# Generated by FakeRAM 2.0 (routing-friendly)
VERSION 5.7 ;
BUSBITCHARS "[]" ;
PROPERTYDEFINITIONS
  MACRO width INTEGER ;
  MACRO depth INTEGER ;
  MACRO banks INTEGER ;
END PROPERTYDEFINITIONS
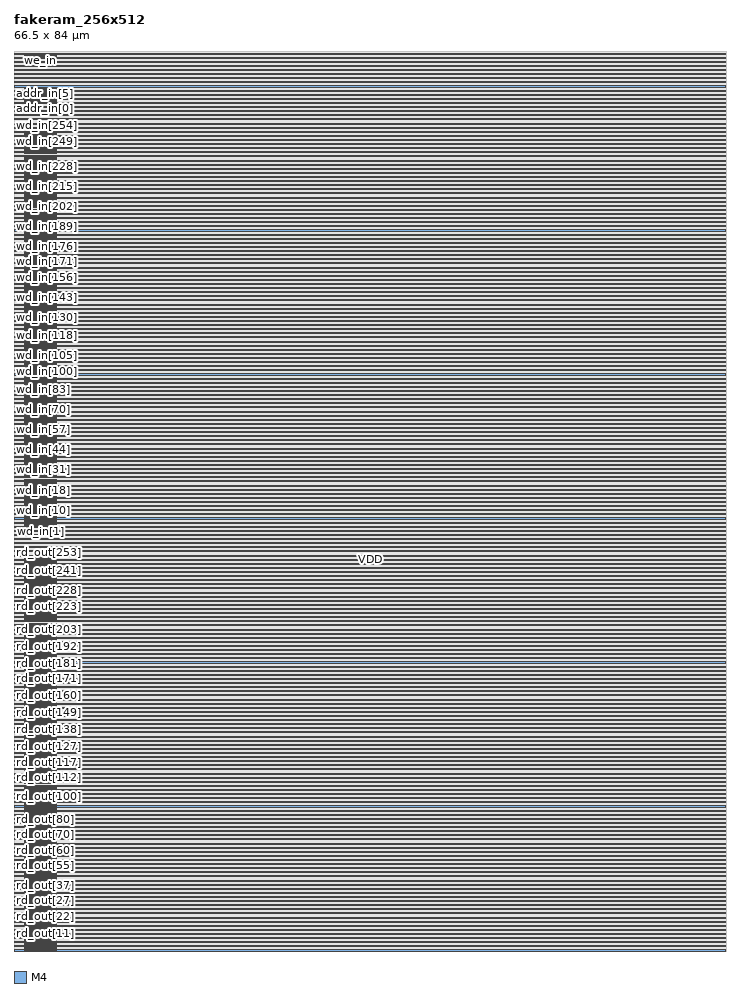
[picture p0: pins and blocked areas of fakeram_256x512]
MACRO fakeram_256x512
  PROPERTY width 256 ;
  PROPERTY depth 512 ;
  PROPERTY banks 2 ;
  FOREIGN fakeram_256x512 0 0 ;
  SYMMETRY X Y R90 ;
  SIZE 66.500 BY 84.000 ;
  CLASS BLOCK ;
  PIN rd_out[0]
    DIRECTION OUTPUT ;
    USE SIGNAL ;
    PORT
      LAYER M4 ;
      RECT 1.000 0.048 3.000 0.072 ;
    END
    PORT
      LAYER M4 ;
      RECT 1.000 0.036 4.000 0.084 ;
    END
  END rd_out[0]
  PIN rd_out[1]
    DIRECTION OUTPUT ;
    USE SIGNAL ;
    PORT
      LAYER M4 ;
      RECT 1.000 0.192 3.000 0.216 ;
    END
    PORT
      LAYER M4 ;
      RECT 1.000 0.180 4.000 0.228 ;
    END
  END rd_out[1]
  PIN rd_out[2]
    DIRECTION OUTPUT ;
    USE SIGNAL ;
    PORT
      LAYER M4 ;
      RECT 1.000 0.336 3.000 0.360 ;
    END
    PORT
      LAYER M4 ;
      RECT 1.000 0.324 4.000 0.372 ;
    END
  END rd_out[2]
  PIN rd_out[3]
    DIRECTION OUTPUT ;
    USE SIGNAL ;
    PORT
      LAYER M4 ;
      RECT 1.000 0.480 3.000 0.504 ;
    END
    PORT
      LAYER M4 ;
      RECT 1.000 0.468 4.000 0.516 ;
    END
  END rd_out[3]
  PIN rd_out[4]
    DIRECTION OUTPUT ;
    USE SIGNAL ;
    PORT
      LAYER M4 ;
      RECT 1.000 0.624 3.000 0.648 ;
    END
    PORT
      LAYER M4 ;
      RECT 1.000 0.612 4.000 0.660 ;
    END
  END rd_out[4]
  PIN rd_out[5]
    DIRECTION OUTPUT ;
    USE SIGNAL ;
    PORT
      LAYER M4 ;
      RECT 1.000 0.768 3.000 0.792 ;
    END
    PORT
      LAYER M4 ;
      RECT 1.000 0.756 4.000 0.804 ;
    END
  END rd_out[5]
  PIN rd_out[6]
    DIRECTION OUTPUT ;
    USE SIGNAL ;
    PORT
      LAYER M4 ;
      RECT 1.000 0.912 3.000 0.936 ;
    END
    PORT
      LAYER M4 ;
      RECT 1.000 0.900 4.000 0.948 ;
    END
  END rd_out[6]
  PIN rd_out[7]
    DIRECTION OUTPUT ;
    USE SIGNAL ;
    PORT
      LAYER M4 ;
      RECT 1.000 1.056 3.000 1.080 ;
    END
    PORT
      LAYER M4 ;
      RECT 1.000 1.044 4.000 1.092 ;
    END
  END rd_out[7]
  PIN rd_out[8]
    DIRECTION OUTPUT ;
    USE SIGNAL ;
    PORT
      LAYER M4 ;
      RECT 1.000 1.200 3.000 1.224 ;
    END
    PORT
      LAYER M4 ;
      RECT 1.000 1.188 4.000 1.236 ;
    END
  END rd_out[8]
  PIN rd_out[9]
    DIRECTION OUTPUT ;
    USE SIGNAL ;
    PORT
      LAYER M4 ;
      RECT 1.000 1.344 3.000 1.368 ;
    END
    PORT
      LAYER M4 ;
      RECT 1.000 1.332 4.000 1.380 ;
    END
  END rd_out[9]
  PIN rd_out[10]
    DIRECTION OUTPUT ;
    USE SIGNAL ;
    PORT
      LAYER M4 ;
      RECT 1.000 1.488 3.000 1.512 ;
    END
    PORT
      LAYER M4 ;
      RECT 1.000 1.476 4.000 1.524 ;
    END
  END rd_out[10]
  PIN rd_out[11]
    DIRECTION OUTPUT ;
    USE SIGNAL ;
    PORT
      LAYER M4 ;
      RECT 1.000 1.632 3.000 1.656 ;
    END
    PORT
      LAYER M4 ;
      RECT 1.000 1.620 4.000 1.668 ;
    END
  END rd_out[11]
  PIN rd_out[12]
    DIRECTION OUTPUT ;
    USE SIGNAL ;
    PORT
      LAYER M4 ;
      RECT 1.000 1.776 3.000 1.800 ;
    END
    PORT
      LAYER M4 ;
      RECT 1.000 1.764 4.000 1.812 ;
    END
  END rd_out[12]
  PIN rd_out[13]
    DIRECTION OUTPUT ;
    USE SIGNAL ;
    PORT
      LAYER M4 ;
      RECT 1.000 1.920 3.000 1.944 ;
    END
    PORT
      LAYER M4 ;
      RECT 1.000 1.908 4.000 1.956 ;
    END
  END rd_out[13]
  PIN rd_out[14]
    DIRECTION OUTPUT ;
    USE SIGNAL ;
    PORT
      LAYER M4 ;
      RECT 1.000 2.064 3.000 2.088 ;
    END
    PORT
      LAYER M4 ;
      RECT 1.000 2.052 4.000 2.100 ;
    END
  END rd_out[14]
  PIN rd_out[15]
    DIRECTION OUTPUT ;
    USE SIGNAL ;
    PORT
      LAYER M4 ;
      RECT 1.000 2.208 3.000 2.232 ;
    END
    PORT
      LAYER M4 ;
      RECT 1.000 2.196 4.000 2.244 ;
    END
  END rd_out[15]
  PIN rd_out[16]
    DIRECTION OUTPUT ;
    USE SIGNAL ;
    PORT
      LAYER M4 ;
      RECT 1.000 2.352 3.000 2.376 ;
    END
    PORT
      LAYER M4 ;
      RECT 1.000 2.340 4.000 2.388 ;
    END
  END rd_out[16]
  PIN rd_out[17]
    DIRECTION OUTPUT ;
    USE SIGNAL ;
    PORT
      LAYER M4 ;
      RECT 1.000 2.496 3.000 2.520 ;
    END
    PORT
      LAYER M4 ;
      RECT 1.000 2.484 4.000 2.532 ;
    END
  END rd_out[17]
  PIN rd_out[18]
    DIRECTION OUTPUT ;
    USE SIGNAL ;
    PORT
      LAYER M4 ;
      RECT 1.000 2.640 3.000 2.664 ;
    END
    PORT
      LAYER M4 ;
      RECT 1.000 2.628 4.000 2.676 ;
    END
  END rd_out[18]
  PIN rd_out[19]
    DIRECTION OUTPUT ;
    USE SIGNAL ;
    PORT
      LAYER M4 ;
      RECT 1.000 2.784 3.000 2.808 ;
    END
    PORT
      LAYER M4 ;
      RECT 1.000 2.772 4.000 2.820 ;
    END
  END rd_out[19]
  PIN rd_out[20]
    DIRECTION OUTPUT ;
    USE SIGNAL ;
    PORT
      LAYER M4 ;
      RECT 1.000 2.928 3.000 2.952 ;
    END
    PORT
      LAYER M4 ;
      RECT 1.000 2.916 4.000 2.964 ;
    END
  END rd_out[20]
  PIN rd_out[21]
    DIRECTION OUTPUT ;
    USE SIGNAL ;
    PORT
      LAYER M4 ;
      RECT 1.000 3.072 3.000 3.096 ;
    END
    PORT
      LAYER M4 ;
      RECT 1.000 3.060 4.000 3.108 ;
    END
  END rd_out[21]
  PIN rd_out[22]
    DIRECTION OUTPUT ;
    USE SIGNAL ;
    PORT
      LAYER M4 ;
      RECT 1.000 3.216 3.000 3.240 ;
    END
    PORT
      LAYER M4 ;
      RECT 1.000 3.204 4.000 3.252 ;
    END
  END rd_out[22]
  PIN rd_out[23]
    DIRECTION OUTPUT ;
    USE SIGNAL ;
    PORT
      LAYER M4 ;
      RECT 1.000 3.360 3.000 3.384 ;
    END
    PORT
      LAYER M4 ;
      RECT 1.000 3.348 4.000 3.396 ;
    END
  END rd_out[23]
  PIN rd_out[24]
    DIRECTION OUTPUT ;
    USE SIGNAL ;
    PORT
      LAYER M4 ;
      RECT 1.000 3.504 3.000 3.528 ;
    END
    PORT
      LAYER M4 ;
      RECT 1.000 3.492 4.000 3.540 ;
    END
  END rd_out[24]
  PIN rd_out[25]
    DIRECTION OUTPUT ;
    USE SIGNAL ;
    PORT
      LAYER M4 ;
      RECT 1.000 3.648 3.000 3.672 ;
    END
    PORT
      LAYER M4 ;
      RECT 1.000 3.636 4.000 3.684 ;
    END
  END rd_out[25]
  PIN rd_out[26]
    DIRECTION OUTPUT ;
    USE SIGNAL ;
    PORT
      LAYER M4 ;
      RECT 1.000 3.792 3.000 3.816 ;
    END
    PORT
      LAYER M4 ;
      RECT 1.000 3.780 4.000 3.828 ;
    END
  END rd_out[26]
  PIN rd_out[27]
    DIRECTION OUTPUT ;
    USE SIGNAL ;
    PORT
      LAYER M4 ;
      RECT 1.000 3.936 3.000 3.960 ;
    END
    PORT
      LAYER M4 ;
      RECT 1.000 3.924 4.000 3.972 ;
    END
  END rd_out[27]
  PIN rd_out[28]
    DIRECTION OUTPUT ;
    USE SIGNAL ;
    PORT
      LAYER M4 ;
      RECT 1.000 4.080 3.000 4.104 ;
    END
    PORT
      LAYER M4 ;
      RECT 1.000 4.068 4.000 4.116 ;
    END
  END rd_out[28]
  PIN rd_out[29]
    DIRECTION OUTPUT ;
    USE SIGNAL ;
    PORT
      LAYER M4 ;
      RECT 1.000 4.224 3.000 4.248 ;
    END
    PORT
      LAYER M4 ;
      RECT 1.000 4.212 4.000 4.260 ;
    END
  END rd_out[29]
  PIN rd_out[30]
    DIRECTION OUTPUT ;
    USE SIGNAL ;
    PORT
      LAYER M4 ;
      RECT 1.000 4.368 3.000 4.392 ;
    END
    PORT
      LAYER M4 ;
      RECT 1.000 4.356 4.000 4.404 ;
    END
  END rd_out[30]
  PIN rd_out[31]
    DIRECTION OUTPUT ;
    USE SIGNAL ;
    PORT
      LAYER M4 ;
      RECT 1.000 4.512 3.000 4.536 ;
    END
    PORT
      LAYER M4 ;
      RECT 1.000 4.500 4.000 4.548 ;
    END
  END rd_out[31]
  PIN rd_out[32]
    DIRECTION OUTPUT ;
    USE SIGNAL ;
    PORT
      LAYER M4 ;
      RECT 1.000 4.656 3.000 4.680 ;
    END
    PORT
      LAYER M4 ;
      RECT 1.000 4.644 4.000 4.692 ;
    END
  END rd_out[32]
  PIN rd_out[33]
    DIRECTION OUTPUT ;
    USE SIGNAL ;
    PORT
      LAYER M4 ;
      RECT 1.000 4.800 3.000 4.824 ;
    END
    PORT
      LAYER M4 ;
      RECT 1.000 4.788 4.000 4.836 ;
    END
  END rd_out[33]
  PIN rd_out[34]
    DIRECTION OUTPUT ;
    USE SIGNAL ;
    PORT
      LAYER M4 ;
      RECT 1.000 4.944 3.000 4.968 ;
    END
    PORT
      LAYER M4 ;
      RECT 1.000 4.932 4.000 4.980 ;
    END
  END rd_out[34]
  PIN rd_out[35]
    DIRECTION OUTPUT ;
    USE SIGNAL ;
    PORT
      LAYER M4 ;
      RECT 1.000 5.088 3.000 5.112 ;
    END
    PORT
      LAYER M4 ;
      RECT 1.000 5.076 4.000 5.124 ;
    END
  END rd_out[35]
  PIN rd_out[36]
    DIRECTION OUTPUT ;
    USE SIGNAL ;
    PORT
      LAYER M4 ;
      RECT 1.000 5.232 3.000 5.256 ;
    END
    PORT
      LAYER M4 ;
      RECT 1.000 5.220 4.000 5.268 ;
    END
  END rd_out[36]
  PIN rd_out[37]
    DIRECTION OUTPUT ;
    USE SIGNAL ;
    PORT
      LAYER M4 ;
      RECT 1.000 5.376 3.000 5.400 ;
    END
    PORT
      LAYER M4 ;
      RECT 1.000 5.364 4.000 5.412 ;
    END
  END rd_out[37]
  PIN rd_out[38]
    DIRECTION OUTPUT ;
    USE SIGNAL ;
    PORT
      LAYER M4 ;
      RECT 1.000 5.520 3.000 5.544 ;
    END
    PORT
      LAYER M4 ;
      RECT 1.000 5.508 4.000 5.556 ;
    END
  END rd_out[38]
  PIN rd_out[39]
    DIRECTION OUTPUT ;
    USE SIGNAL ;
    PORT
      LAYER M4 ;
      RECT 1.000 5.664 3.000 5.688 ;
    END
    PORT
      LAYER M4 ;
      RECT 1.000 5.652 4.000 5.700 ;
    END
  END rd_out[39]
  PIN rd_out[40]
    DIRECTION OUTPUT ;
    USE SIGNAL ;
    PORT
      LAYER M4 ;
      RECT 1.000 5.808 3.000 5.832 ;
    END
    PORT
      LAYER M4 ;
      RECT 1.000 5.796 4.000 5.844 ;
    END
  END rd_out[40]
  PIN rd_out[41]
    DIRECTION OUTPUT ;
    USE SIGNAL ;
    PORT
      LAYER M4 ;
      RECT 1.000 5.952 3.000 5.976 ;
    END
    PORT
      LAYER M4 ;
      RECT 1.000 5.940 4.000 5.988 ;
    END
  END rd_out[41]
  PIN rd_out[42]
    DIRECTION OUTPUT ;
    USE SIGNAL ;
    PORT
      LAYER M4 ;
      RECT 1.000 6.096 3.000 6.120 ;
    END
    PORT
      LAYER M4 ;
      RECT 1.000 6.084 4.000 6.132 ;
    END
  END rd_out[42]
  PIN rd_out[43]
    DIRECTION OUTPUT ;
    USE SIGNAL ;
    PORT
      LAYER M4 ;
      RECT 1.000 6.240 3.000 6.264 ;
    END
    PORT
      LAYER M4 ;
      RECT 1.000 6.228 4.000 6.276 ;
    END
  END rd_out[43]
  PIN rd_out[44]
    DIRECTION OUTPUT ;
    USE SIGNAL ;
    PORT
      LAYER M4 ;
      RECT 1.000 6.384 3.000 6.408 ;
    END
    PORT
      LAYER M4 ;
      RECT 1.000 6.372 4.000 6.420 ;
    END
  END rd_out[44]
  PIN rd_out[45]
    DIRECTION OUTPUT ;
    USE SIGNAL ;
    PORT
      LAYER M4 ;
      RECT 1.000 6.528 3.000 6.552 ;
    END
    PORT
      LAYER M4 ;
      RECT 1.000 6.516 4.000 6.564 ;
    END
  END rd_out[45]
  PIN rd_out[46]
    DIRECTION OUTPUT ;
    USE SIGNAL ;
    PORT
      LAYER M4 ;
      RECT 1.000 6.672 3.000 6.696 ;
    END
    PORT
      LAYER M4 ;
      RECT 1.000 6.660 4.000 6.708 ;
    END
  END rd_out[46]
  PIN rd_out[47]
    DIRECTION OUTPUT ;
    USE SIGNAL ;
    PORT
      LAYER M4 ;
      RECT 1.000 6.816 3.000 6.840 ;
    END
    PORT
      LAYER M4 ;
      RECT 1.000 6.804 4.000 6.852 ;
    END
  END rd_out[47]
  PIN rd_out[48]
    DIRECTION OUTPUT ;
    USE SIGNAL ;
    PORT
      LAYER M4 ;
      RECT 1.000 6.960 3.000 6.984 ;
    END
    PORT
      LAYER M4 ;
      RECT 1.000 6.948 4.000 6.996 ;
    END
  END rd_out[48]
  PIN rd_out[49]
    DIRECTION OUTPUT ;
    USE SIGNAL ;
    PORT
      LAYER M4 ;
      RECT 1.000 7.104 3.000 7.128 ;
    END
    PORT
      LAYER M4 ;
      RECT 1.000 7.092 4.000 7.140 ;
    END
  END rd_out[49]
  PIN rd_out[50]
    DIRECTION OUTPUT ;
    USE SIGNAL ;
    PORT
      LAYER M4 ;
      RECT 1.000 7.248 3.000 7.272 ;
    END
    PORT
      LAYER M4 ;
      RECT 1.000 7.236 4.000 7.284 ;
    END
  END rd_out[50]
  PIN rd_out[51]
    DIRECTION OUTPUT ;
    USE SIGNAL ;
    PORT
      LAYER M4 ;
      RECT 1.000 7.392 3.000 7.416 ;
    END
    PORT
      LAYER M4 ;
      RECT 1.000 7.380 4.000 7.428 ;
    END
  END rd_out[51]
  PIN rd_out[52]
    DIRECTION OUTPUT ;
    USE SIGNAL ;
    PORT
      LAYER M4 ;
      RECT 1.000 7.536 3.000 7.560 ;
    END
    PORT
      LAYER M4 ;
      RECT 1.000 7.524 4.000 7.572 ;
    END
  END rd_out[52]
  PIN rd_out[53]
    DIRECTION OUTPUT ;
    USE SIGNAL ;
    PORT
      LAYER M4 ;
      RECT 1.000 7.680 3.000 7.704 ;
    END
    PORT
      LAYER M4 ;
      RECT 1.000 7.668 4.000 7.716 ;
    END
  END rd_out[53]
  PIN rd_out[54]
    DIRECTION OUTPUT ;
    USE SIGNAL ;
    PORT
      LAYER M4 ;
      RECT 1.000 7.824 3.000 7.848 ;
    END
    PORT
      LAYER M4 ;
      RECT 1.000 7.812 4.000 7.860 ;
    END
  END rd_out[54]
  PIN rd_out[55]
    DIRECTION OUTPUT ;
    USE SIGNAL ;
    PORT
      LAYER M4 ;
      RECT 1.000 7.968 3.000 7.992 ;
    END
    PORT
      LAYER M4 ;
      RECT 1.000 7.956 4.000 8.004 ;
    END
  END rd_out[55]
  PIN rd_out[56]
    DIRECTION OUTPUT ;
    USE SIGNAL ;
    PORT
      LAYER M4 ;
      RECT 1.000 8.112 3.000 8.136 ;
    END
    PORT
      LAYER M4 ;
      RECT 1.000 8.100 4.000 8.148 ;
    END
  END rd_out[56]
  PIN rd_out[57]
    DIRECTION OUTPUT ;
    USE SIGNAL ;
    PORT
      LAYER M4 ;
      RECT 1.000 8.256 3.000 8.280 ;
    END
    PORT
      LAYER M4 ;
      RECT 1.000 8.244 4.000 8.292 ;
    END
  END rd_out[57]
  PIN rd_out[58]
    DIRECTION OUTPUT ;
    USE SIGNAL ;
    PORT
      LAYER M4 ;
      RECT 1.000 8.400 3.000 8.424 ;
    END
    PORT
      LAYER M4 ;
      RECT 1.000 8.388 4.000 8.436 ;
    END
  END rd_out[58]
  PIN rd_out[59]
    DIRECTION OUTPUT ;
    USE SIGNAL ;
    PORT
      LAYER M4 ;
      RECT 1.000 8.544 3.000 8.568 ;
    END
    PORT
      LAYER M4 ;
      RECT 1.000 8.532 4.000 8.580 ;
    END
  END rd_out[59]
  PIN rd_out[60]
    DIRECTION OUTPUT ;
    USE SIGNAL ;
    PORT
      LAYER M4 ;
      RECT 1.000 8.688 3.000 8.712 ;
    END
    PORT
      LAYER M4 ;
      RECT 1.000 8.676 4.000 8.724 ;
    END
  END rd_out[60]
  PIN rd_out[61]
    DIRECTION OUTPUT ;
    USE SIGNAL ;
    PORT
      LAYER M4 ;
      RECT 1.000 8.832 3.000 8.856 ;
    END
    PORT
      LAYER M4 ;
      RECT 1.000 8.820 4.000 8.868 ;
    END
  END rd_out[61]
  PIN rd_out[62]
    DIRECTION OUTPUT ;
    USE SIGNAL ;
    PORT
      LAYER M4 ;
      RECT 1.000 8.976 3.000 9.000 ;
    END
    PORT
      LAYER M4 ;
      RECT 1.000 8.964 4.000 9.012 ;
    END
  END rd_out[62]
  PIN rd_out[63]
    DIRECTION OUTPUT ;
    USE SIGNAL ;
    PORT
      LAYER M4 ;
      RECT 1.000 9.120 3.000 9.144 ;
    END
    PORT
      LAYER M4 ;
      RECT 1.000 9.108 4.000 9.156 ;
    END
  END rd_out[63]
  PIN rd_out[64]
    DIRECTION OUTPUT ;
    USE SIGNAL ;
    PORT
      LAYER M4 ;
      RECT 1.000 9.264 3.000 9.288 ;
    END
    PORT
      LAYER M4 ;
      RECT 1.000 9.252 4.000 9.300 ;
    END
  END rd_out[64]
  PIN rd_out[65]
    DIRECTION OUTPUT ;
    USE SIGNAL ;
    PORT
      LAYER M4 ;
      RECT 1.000 9.408 3.000 9.432 ;
    END
    PORT
      LAYER M4 ;
      RECT 1.000 9.396 4.000 9.444 ;
    END
  END rd_out[65]
  PIN rd_out[66]
    DIRECTION OUTPUT ;
    USE SIGNAL ;
    PORT
      LAYER M4 ;
      RECT 1.000 9.552 3.000 9.576 ;
    END
    PORT
      LAYER M4 ;
      RECT 1.000 9.540 4.000 9.588 ;
    END
  END rd_out[66]
  PIN rd_out[67]
    DIRECTION OUTPUT ;
    USE SIGNAL ;
    PORT
      LAYER M4 ;
      RECT 1.000 9.696 3.000 9.720 ;
    END
    PORT
      LAYER M4 ;
      RECT 1.000 9.684 4.000 9.732 ;
    END
  END rd_out[67]
  PIN rd_out[68]
    DIRECTION OUTPUT ;
    USE SIGNAL ;
    PORT
      LAYER M4 ;
      RECT 1.000 9.840 3.000 9.864 ;
    END
    PORT
      LAYER M4 ;
      RECT 1.000 9.828 4.000 9.876 ;
    END
  END rd_out[68]
  PIN rd_out[69]
    DIRECTION OUTPUT ;
    USE SIGNAL ;
    PORT
      LAYER M4 ;
      RECT 1.000 9.984 3.000 10.008 ;
    END
    PORT
      LAYER M4 ;
      RECT 1.000 9.972 4.000 10.020 ;
    END
  END rd_out[69]
  PIN rd_out[70]
    DIRECTION OUTPUT ;
    USE SIGNAL ;
    PORT
      LAYER M4 ;
      RECT 1.000 10.128 3.000 10.152 ;
    END
    PORT
      LAYER M4 ;
      RECT 1.000 10.116 4.000 10.164 ;
    END
  END rd_out[70]
  PIN rd_out[71]
    DIRECTION OUTPUT ;
    USE SIGNAL ;
    PORT
      LAYER M4 ;
      RECT 1.000 10.272 3.000 10.296 ;
    END
    PORT
      LAYER M4 ;
      RECT 1.000 10.260 4.000 10.308 ;
    END
  END rd_out[71]
  PIN rd_out[72]
    DIRECTION OUTPUT ;
    USE SIGNAL ;
    PORT
      LAYER M4 ;
      RECT 1.000 10.416 3.000 10.440 ;
    END
    PORT
      LAYER M4 ;
      RECT 1.000 10.404 4.000 10.452 ;
    END
  END rd_out[72]
  PIN rd_out[73]
    DIRECTION OUTPUT ;
    USE SIGNAL ;
    PORT
      LAYER M4 ;
      RECT 1.000 10.560 3.000 10.584 ;
    END
    PORT
      LAYER M4 ;
      RECT 1.000 10.548 4.000 10.596 ;
    END
  END rd_out[73]
  PIN rd_out[74]
    DIRECTION OUTPUT ;
    USE SIGNAL ;
    PORT
      LAYER M4 ;
      RECT 1.000 10.704 3.000 10.728 ;
    END
    PORT
      LAYER M4 ;
      RECT 1.000 10.692 4.000 10.740 ;
    END
  END rd_out[74]
  PIN rd_out[75]
    DIRECTION OUTPUT ;
    USE SIGNAL ;
    PORT
      LAYER M4 ;
      RECT 1.000 10.848 3.000 10.872 ;
    END
    PORT
      LAYER M4 ;
      RECT 1.000 10.836 4.000 10.884 ;
    END
  END rd_out[75]
  PIN rd_out[76]
    DIRECTION OUTPUT ;
    USE SIGNAL ;
    PORT
      LAYER M4 ;
      RECT 1.000 10.992 3.000 11.016 ;
    END
    PORT
      LAYER M4 ;
      RECT 1.000 10.980 4.000 11.028 ;
    END
  END rd_out[76]
  PIN rd_out[77]
    DIRECTION OUTPUT ;
    USE SIGNAL ;
    PORT
      LAYER M4 ;
      RECT 1.000 11.136 3.000 11.160 ;
    END
    PORT
      LAYER M4 ;
      RECT 1.000 11.124 4.000 11.172 ;
    END
  END rd_out[77]
  PIN rd_out[78]
    DIRECTION OUTPUT ;
    USE SIGNAL ;
    PORT
      LAYER M4 ;
      RECT 1.000 11.280 3.000 11.304 ;
    END
    PORT
      LAYER M4 ;
      RECT 1.000 11.268 4.000 11.316 ;
    END
  END rd_out[78]
  PIN rd_out[79]
    DIRECTION OUTPUT ;
    USE SIGNAL ;
    PORT
      LAYER M4 ;
      RECT 1.000 11.424 3.000 11.448 ;
    END
    PORT
      LAYER M4 ;
      RECT 1.000 11.412 4.000 11.460 ;
    END
  END rd_out[79]
  PIN rd_out[80]
    DIRECTION OUTPUT ;
    USE SIGNAL ;
    PORT
      LAYER M4 ;
      RECT 1.000 11.568 3.000 11.592 ;
    END
    PORT
      LAYER M4 ;
      RECT 1.000 11.556 4.000 11.604 ;
    END
  END rd_out[80]
  PIN rd_out[81]
    DIRECTION OUTPUT ;
    USE SIGNAL ;
    PORT
      LAYER M4 ;
      RECT 1.000 11.712 3.000 11.736 ;
    END
    PORT
      LAYER M4 ;
      RECT 1.000 11.700 4.000 11.748 ;
    END
  END rd_out[81]
  PIN rd_out[82]
    DIRECTION OUTPUT ;
    USE SIGNAL ;
    PORT
      LAYER M4 ;
      RECT 1.000 11.856 3.000 11.880 ;
    END
    PORT
      LAYER M4 ;
      RECT 1.000 11.844 4.000 11.892 ;
    END
  END rd_out[82]
  PIN rd_out[83]
    DIRECTION OUTPUT ;
    USE SIGNAL ;
    PORT
      LAYER M4 ;
      RECT 1.000 12.000 3.000 12.024 ;
    END
    PORT
      LAYER M4 ;
      RECT 1.000 11.988 4.000 12.036 ;
    END
  END rd_out[83]
  PIN rd_out[84]
    DIRECTION OUTPUT ;
    USE SIGNAL ;
    PORT
      LAYER M4 ;
      RECT 1.000 12.144 3.000 12.168 ;
    END
    PORT
      LAYER M4 ;
      RECT 1.000 12.132 4.000 12.180 ;
    END
  END rd_out[84]
  PIN rd_out[85]
    DIRECTION OUTPUT ;
    USE SIGNAL ;
    PORT
      LAYER M4 ;
      RECT 1.000 12.288 3.000 12.312 ;
    END
    PORT
      LAYER M4 ;
      RECT 1.000 12.276 4.000 12.324 ;
    END
  END rd_out[85]
  PIN rd_out[86]
    DIRECTION OUTPUT ;
    USE SIGNAL ;
    PORT
      LAYER M4 ;
      RECT 1.000 12.432 3.000 12.456 ;
    END
    PORT
      LAYER M4 ;
      RECT 1.000 12.420 4.000 12.468 ;
    END
  END rd_out[86]
  PIN rd_out[87]
    DIRECTION OUTPUT ;
    USE SIGNAL ;
    PORT
      LAYER M4 ;
      RECT 1.000 12.576 3.000 12.600 ;
    END
    PORT
      LAYER M4 ;
      RECT 1.000 12.564 4.000 12.612 ;
    END
  END rd_out[87]
  PIN rd_out[88]
    DIRECTION OUTPUT ;
    USE SIGNAL ;
    PORT
      LAYER M4 ;
      RECT 1.000 12.720 3.000 12.744 ;
    END
    PORT
      LAYER M4 ;
      RECT 1.000 12.708 4.000 12.756 ;
    END
  END rd_out[88]
  PIN rd_out[89]
    DIRECTION OUTPUT ;
    USE SIGNAL ;
    PORT
      LAYER M4 ;
      RECT 1.000 12.864 3.000 12.888 ;
    END
    PORT
      LAYER M4 ;
      RECT 1.000 12.852 4.000 12.900 ;
    END
  END rd_out[89]
  PIN rd_out[90]
    DIRECTION OUTPUT ;
    USE SIGNAL ;
    PORT
      LAYER M4 ;
      RECT 1.000 13.008 3.000 13.032 ;
    END
    PORT
      LAYER M4 ;
      RECT 1.000 12.996 4.000 13.044 ;
    END
  END rd_out[90]
  PIN rd_out[91]
    DIRECTION OUTPUT ;
    USE SIGNAL ;
    PORT
      LAYER M4 ;
      RECT 1.000 13.152 3.000 13.176 ;
    END
    PORT
      LAYER M4 ;
      RECT 1.000 13.140 4.000 13.188 ;
    END
  END rd_out[91]
  PIN rd_out[92]
    DIRECTION OUTPUT ;
    USE SIGNAL ;
    PORT
      LAYER M4 ;
      RECT 1.000 13.296 3.000 13.320 ;
    END
    PORT
      LAYER M4 ;
      RECT 1.000 13.284 4.000 13.332 ;
    END
  END rd_out[92]
  PIN rd_out[93]
    DIRECTION OUTPUT ;
    USE SIGNAL ;
    PORT
      LAYER M4 ;
      RECT 1.000 13.440 3.000 13.464 ;
    END
    PORT
      LAYER M4 ;
      RECT 1.000 13.428 4.000 13.476 ;
    END
  END rd_out[93]
  PIN rd_out[94]
    DIRECTION OUTPUT ;
    USE SIGNAL ;
    PORT
      LAYER M4 ;
      RECT 1.000 13.584 3.000 13.608 ;
    END
    PORT
      LAYER M4 ;
      RECT 1.000 13.572 4.000 13.620 ;
    END
  END rd_out[94]
  PIN rd_out[95]
    DIRECTION OUTPUT ;
    USE SIGNAL ;
    PORT
      LAYER M4 ;
      RECT 1.000 13.728 3.000 13.752 ;
    END
    PORT
      LAYER M4 ;
      RECT 1.000 13.716 4.000 13.764 ;
    END
  END rd_out[95]
  PIN rd_out[96]
    DIRECTION OUTPUT ;
    USE SIGNAL ;
    PORT
      LAYER M4 ;
      RECT 1.000 13.872 3.000 13.896 ;
    END
    PORT
      LAYER M4 ;
      RECT 1.000 13.860 4.000 13.908 ;
    END
  END rd_out[96]
  PIN rd_out[97]
    DIRECTION OUTPUT ;
    USE SIGNAL ;
    PORT
      LAYER M4 ;
      RECT 1.000 14.016 3.000 14.040 ;
    END
    PORT
      LAYER M4 ;
      RECT 1.000 14.004 4.000 14.052 ;
    END
  END rd_out[97]
  PIN rd_out[98]
    DIRECTION OUTPUT ;
    USE SIGNAL ;
    PORT
      LAYER M4 ;
      RECT 1.000 14.160 3.000 14.184 ;
    END
    PORT
      LAYER M4 ;
      RECT 1.000 14.148 4.000 14.196 ;
    END
  END rd_out[98]
  PIN rd_out[99]
    DIRECTION OUTPUT ;
    USE SIGNAL ;
    PORT
      LAYER M4 ;
      RECT 1.000 14.304 3.000 14.328 ;
    END
    PORT
      LAYER M4 ;
      RECT 1.000 14.292 4.000 14.340 ;
    END
  END rd_out[99]
  PIN rd_out[100]
    DIRECTION OUTPUT ;
    USE SIGNAL ;
    PORT
      LAYER M4 ;
      RECT 1.000 14.448 3.000 14.472 ;
    END
    PORT
      LAYER M4 ;
      RECT 1.000 14.436 4.000 14.484 ;
    END
  END rd_out[100]
  PIN rd_out[101]
    DIRECTION OUTPUT ;
    USE SIGNAL ;
    PORT
      LAYER M4 ;
      RECT 1.000 14.592 3.000 14.616 ;
    END
    PORT
      LAYER M4 ;
      RECT 1.000 14.580 4.000 14.628 ;
    END
  END rd_out[101]
  PIN rd_out[102]
    DIRECTION OUTPUT ;
    USE SIGNAL ;
    PORT
      LAYER M4 ;
      RECT 1.000 14.736 3.000 14.760 ;
    END
    PORT
      LAYER M4 ;
      RECT 1.000 14.724 4.000 14.772 ;
    END
  END rd_out[102]
  PIN rd_out[103]
    DIRECTION OUTPUT ;
    USE SIGNAL ;
    PORT
      LAYER M4 ;
      RECT 1.000 14.880 3.000 14.904 ;
    END
    PORT
      LAYER M4 ;
      RECT 1.000 14.868 4.000 14.916 ;
    END
  END rd_out[103]
  PIN rd_out[104]
    DIRECTION OUTPUT ;
    USE SIGNAL ;
    PORT
      LAYER M4 ;
      RECT 1.000 15.024 3.000 15.048 ;
    END
    PORT
      LAYER M4 ;
      RECT 1.000 15.012 4.000 15.060 ;
    END
  END rd_out[104]
  PIN rd_out[105]
    DIRECTION OUTPUT ;
    USE SIGNAL ;
    PORT
      LAYER M4 ;
      RECT 1.000 15.168 3.000 15.192 ;
    END
    PORT
      LAYER M4 ;
      RECT 1.000 15.156 4.000 15.204 ;
    END
  END rd_out[105]
  PIN rd_out[106]
    DIRECTION OUTPUT ;
    USE SIGNAL ;
    PORT
      LAYER M4 ;
      RECT 1.000 15.312 3.000 15.336 ;
    END
    PORT
      LAYER M4 ;
      RECT 1.000 15.300 4.000 15.348 ;
    END
  END rd_out[106]
  PIN rd_out[107]
    DIRECTION OUTPUT ;
    USE SIGNAL ;
    PORT
      LAYER M4 ;
      RECT 1.000 15.456 3.000 15.480 ;
    END
    PORT
      LAYER M4 ;
      RECT 1.000 15.444 4.000 15.492 ;
    END
  END rd_out[107]
  PIN rd_out[108]
    DIRECTION OUTPUT ;
    USE SIGNAL ;
    PORT
      LAYER M4 ;
      RECT 1.000 15.600 3.000 15.624 ;
    END
    PORT
      LAYER M4 ;
      RECT 1.000 15.588 4.000 15.636 ;
    END
  END rd_out[108]
  PIN rd_out[109]
    DIRECTION OUTPUT ;
    USE SIGNAL ;
    PORT
      LAYER M4 ;
      RECT 1.000 15.744 3.000 15.768 ;
    END
    PORT
      LAYER M4 ;
      RECT 1.000 15.732 4.000 15.780 ;
    END
  END rd_out[109]
  PIN rd_out[110]
    DIRECTION OUTPUT ;
    USE SIGNAL ;
    PORT
      LAYER M4 ;
      RECT 1.000 15.888 3.000 15.912 ;
    END
    PORT
      LAYER M4 ;
      RECT 1.000 15.876 4.000 15.924 ;
    END
  END rd_out[110]
  PIN rd_out[111]
    DIRECTION OUTPUT ;
    USE SIGNAL ;
    PORT
      LAYER M4 ;
      RECT 1.000 16.032 3.000 16.056 ;
    END
    PORT
      LAYER M4 ;
      RECT 1.000 16.020 4.000 16.068 ;
    END
  END rd_out[111]
  PIN rd_out[112]
    DIRECTION OUTPUT ;
    USE SIGNAL ;
    PORT
      LAYER M4 ;
      RECT 1.000 16.176 3.000 16.200 ;
    END
    PORT
      LAYER M4 ;
      RECT 1.000 16.164 4.000 16.212 ;
    END
  END rd_out[112]
  PIN rd_out[113]
    DIRECTION OUTPUT ;
    USE SIGNAL ;
    PORT
      LAYER M4 ;
      RECT 1.000 16.320 3.000 16.344 ;
    END
    PORT
      LAYER M4 ;
      RECT 1.000 16.308 4.000 16.356 ;
    END
  END rd_out[113]
  PIN rd_out[114]
    DIRECTION OUTPUT ;
    USE SIGNAL ;
    PORT
      LAYER M4 ;
      RECT 1.000 16.464 3.000 16.488 ;
    END
    PORT
      LAYER M4 ;
      RECT 1.000 16.452 4.000 16.500 ;
    END
  END rd_out[114]
  PIN rd_out[115]
    DIRECTION OUTPUT ;
    USE SIGNAL ;
    PORT
      LAYER M4 ;
      RECT 1.000 16.608 3.000 16.632 ;
    END
    PORT
      LAYER M4 ;
      RECT 1.000 16.596 4.000 16.644 ;
    END
  END rd_out[115]
  PIN rd_out[116]
    DIRECTION OUTPUT ;
    USE SIGNAL ;
    PORT
      LAYER M4 ;
      RECT 1.000 16.752 3.000 16.776 ;
    END
    PORT
      LAYER M4 ;
      RECT 1.000 16.740 4.000 16.788 ;
    END
  END rd_out[116]
  PIN rd_out[117]
    DIRECTION OUTPUT ;
    USE SIGNAL ;
    PORT
      LAYER M4 ;
      RECT 1.000 16.896 3.000 16.920 ;
    END
    PORT
      LAYER M4 ;
      RECT 1.000 16.884 4.000 16.932 ;
    END
  END rd_out[117]
  PIN rd_out[118]
    DIRECTION OUTPUT ;
    USE SIGNAL ;
    PORT
      LAYER M4 ;
      RECT 1.000 17.040 3.000 17.064 ;
    END
    PORT
      LAYER M4 ;
      RECT 1.000 17.028 4.000 17.076 ;
    END
  END rd_out[118]
  PIN rd_out[119]
    DIRECTION OUTPUT ;
    USE SIGNAL ;
    PORT
      LAYER M4 ;
      RECT 1.000 17.184 3.000 17.208 ;
    END
    PORT
      LAYER M4 ;
      RECT 1.000 17.172 4.000 17.220 ;
    END
  END rd_out[119]
  PIN rd_out[120]
    DIRECTION OUTPUT ;
    USE SIGNAL ;
    PORT
      LAYER M4 ;
      RECT 1.000 17.328 3.000 17.352 ;
    END
    PORT
      LAYER M4 ;
      RECT 1.000 17.316 4.000 17.364 ;
    END
  END rd_out[120]
  PIN rd_out[121]
    DIRECTION OUTPUT ;
    USE SIGNAL ;
    PORT
      LAYER M4 ;
      RECT 1.000 17.472 3.000 17.496 ;
    END
    PORT
      LAYER M4 ;
      RECT 1.000 17.460 4.000 17.508 ;
    END
  END rd_out[121]
  PIN rd_out[122]
    DIRECTION OUTPUT ;
    USE SIGNAL ;
    PORT
      LAYER M4 ;
      RECT 1.000 17.616 3.000 17.640 ;
    END
    PORT
      LAYER M4 ;
      RECT 1.000 17.604 4.000 17.652 ;
    END
  END rd_out[122]
  PIN rd_out[123]
    DIRECTION OUTPUT ;
    USE SIGNAL ;
    PORT
      LAYER M4 ;
      RECT 1.000 17.760 3.000 17.784 ;
    END
    PORT
      LAYER M4 ;
      RECT 1.000 17.748 4.000 17.796 ;
    END
  END rd_out[123]
  PIN rd_out[124]
    DIRECTION OUTPUT ;
    USE SIGNAL ;
    PORT
      LAYER M4 ;
      RECT 1.000 17.904 3.000 17.928 ;
    END
    PORT
      LAYER M4 ;
      RECT 1.000 17.892 4.000 17.940 ;
    END
  END rd_out[124]
  PIN rd_out[125]
    DIRECTION OUTPUT ;
    USE SIGNAL ;
    PORT
      LAYER M4 ;
      RECT 1.000 18.048 3.000 18.072 ;
    END
    PORT
      LAYER M4 ;
      RECT 1.000 18.036 4.000 18.084 ;
    END
  END rd_out[125]
  PIN rd_out[126]
    DIRECTION OUTPUT ;
    USE SIGNAL ;
    PORT
      LAYER M4 ;
      RECT 1.000 18.192 3.000 18.216 ;
    END
    PORT
      LAYER M4 ;
      RECT 1.000 18.180 4.000 18.228 ;
    END
  END rd_out[126]
  PIN rd_out[127]
    DIRECTION OUTPUT ;
    USE SIGNAL ;
    PORT
      LAYER M4 ;
      RECT 1.000 18.336 3.000 18.360 ;
    END
    PORT
      LAYER M4 ;
      RECT 1.000 18.324 4.000 18.372 ;
    END
  END rd_out[127]
  PIN rd_out[128]
    DIRECTION OUTPUT ;
    USE SIGNAL ;
    PORT
      LAYER M4 ;
      RECT 1.000 18.480 3.000 18.504 ;
    END
    PORT
      LAYER M4 ;
      RECT 1.000 18.468 4.000 18.516 ;
    END
  END rd_out[128]
  PIN rd_out[129]
    DIRECTION OUTPUT ;
    USE SIGNAL ;
    PORT
      LAYER M4 ;
      RECT 1.000 18.624 3.000 18.648 ;
    END
    PORT
      LAYER M4 ;
      RECT 1.000 18.612 4.000 18.660 ;
    END
  END rd_out[129]
  PIN rd_out[130]
    DIRECTION OUTPUT ;
    USE SIGNAL ;
    PORT
      LAYER M4 ;
      RECT 1.000 18.768 3.000 18.792 ;
    END
    PORT
      LAYER M4 ;
      RECT 1.000 18.756 4.000 18.804 ;
    END
  END rd_out[130]
  PIN rd_out[131]
    DIRECTION OUTPUT ;
    USE SIGNAL ;
    PORT
      LAYER M4 ;
      RECT 1.000 18.912 3.000 18.936 ;
    END
    PORT
      LAYER M4 ;
      RECT 1.000 18.900 4.000 18.948 ;
    END
  END rd_out[131]
  PIN rd_out[132]
    DIRECTION OUTPUT ;
    USE SIGNAL ;
    PORT
      LAYER M4 ;
      RECT 1.000 19.056 3.000 19.080 ;
    END
    PORT
      LAYER M4 ;
      RECT 1.000 19.044 4.000 19.092 ;
    END
  END rd_out[132]
  PIN rd_out[133]
    DIRECTION OUTPUT ;
    USE SIGNAL ;
    PORT
      LAYER M4 ;
      RECT 1.000 19.200 3.000 19.224 ;
    END
    PORT
      LAYER M4 ;
      RECT 1.000 19.188 4.000 19.236 ;
    END
  END rd_out[133]
  PIN rd_out[134]
    DIRECTION OUTPUT ;
    USE SIGNAL ;
    PORT
      LAYER M4 ;
      RECT 1.000 19.344 3.000 19.368 ;
    END
    PORT
      LAYER M4 ;
      RECT 1.000 19.332 4.000 19.380 ;
    END
  END rd_out[134]
  PIN rd_out[135]
    DIRECTION OUTPUT ;
    USE SIGNAL ;
    PORT
      LAYER M4 ;
      RECT 1.000 19.488 3.000 19.512 ;
    END
    PORT
      LAYER M4 ;
      RECT 1.000 19.476 4.000 19.524 ;
    END
  END rd_out[135]
  PIN rd_out[136]
    DIRECTION OUTPUT ;
    USE SIGNAL ;
    PORT
      LAYER M4 ;
      RECT 1.000 19.632 3.000 19.656 ;
    END
    PORT
      LAYER M4 ;
      RECT 1.000 19.620 4.000 19.668 ;
    END
  END rd_out[136]
  PIN rd_out[137]
    DIRECTION OUTPUT ;
    USE SIGNAL ;
    PORT
      LAYER M4 ;
      RECT 1.000 19.776 3.000 19.800 ;
    END
    PORT
      LAYER M4 ;
      RECT 1.000 19.764 4.000 19.812 ;
    END
  END rd_out[137]
  PIN rd_out[138]
    DIRECTION OUTPUT ;
    USE SIGNAL ;
    PORT
      LAYER M4 ;
      RECT 1.000 19.920 3.000 19.944 ;
    END
    PORT
      LAYER M4 ;
      RECT 1.000 19.908 4.000 19.956 ;
    END
  END rd_out[138]
  PIN rd_out[139]
    DIRECTION OUTPUT ;
    USE SIGNAL ;
    PORT
      LAYER M4 ;
      RECT 1.000 20.064 3.000 20.088 ;
    END
    PORT
      LAYER M4 ;
      RECT 1.000 20.052 4.000 20.100 ;
    END
  END rd_out[139]
  PIN rd_out[140]
    DIRECTION OUTPUT ;
    USE SIGNAL ;
    PORT
      LAYER M4 ;
      RECT 1.000 20.208 3.000 20.232 ;
    END
    PORT
      LAYER M4 ;
      RECT 1.000 20.196 4.000 20.244 ;
    END
  END rd_out[140]
  PIN rd_out[141]
    DIRECTION OUTPUT ;
    USE SIGNAL ;
    PORT
      LAYER M4 ;
      RECT 1.000 20.352 3.000 20.376 ;
    END
    PORT
      LAYER M4 ;
      RECT 1.000 20.340 4.000 20.388 ;
    END
  END rd_out[141]
  PIN rd_out[142]
    DIRECTION OUTPUT ;
    USE SIGNAL ;
    PORT
      LAYER M4 ;
      RECT 1.000 20.496 3.000 20.520 ;
    END
    PORT
      LAYER M4 ;
      RECT 1.000 20.484 4.000 20.532 ;
    END
  END rd_out[142]
  PIN rd_out[143]
    DIRECTION OUTPUT ;
    USE SIGNAL ;
    PORT
      LAYER M4 ;
      RECT 1.000 20.640 3.000 20.664 ;
    END
    PORT
      LAYER M4 ;
      RECT 1.000 20.628 4.000 20.676 ;
    END
  END rd_out[143]
  PIN rd_out[144]
    DIRECTION OUTPUT ;
    USE SIGNAL ;
    PORT
      LAYER M4 ;
      RECT 1.000 20.784 3.000 20.808 ;
    END
    PORT
      LAYER M4 ;
      RECT 1.000 20.772 4.000 20.820 ;
    END
  END rd_out[144]
  PIN rd_out[145]
    DIRECTION OUTPUT ;
    USE SIGNAL ;
    PORT
      LAYER M4 ;
      RECT 1.000 20.928 3.000 20.952 ;
    END
    PORT
      LAYER M4 ;
      RECT 1.000 20.916 4.000 20.964 ;
    END
  END rd_out[145]
  PIN rd_out[146]
    DIRECTION OUTPUT ;
    USE SIGNAL ;
    PORT
      LAYER M4 ;
      RECT 1.000 21.072 3.000 21.096 ;
    END
    PORT
      LAYER M4 ;
      RECT 1.000 21.060 4.000 21.108 ;
    END
  END rd_out[146]
  PIN rd_out[147]
    DIRECTION OUTPUT ;
    USE SIGNAL ;
    PORT
      LAYER M4 ;
      RECT 1.000 21.216 3.000 21.240 ;
    END
    PORT
      LAYER M4 ;
      RECT 1.000 21.204 4.000 21.252 ;
    END
  END rd_out[147]
  PIN rd_out[148]
    DIRECTION OUTPUT ;
    USE SIGNAL ;
    PORT
      LAYER M4 ;
      RECT 1.000 21.360 3.000 21.384 ;
    END
    PORT
      LAYER M4 ;
      RECT 1.000 21.348 4.000 21.396 ;
    END
  END rd_out[148]
  PIN rd_out[149]
    DIRECTION OUTPUT ;
    USE SIGNAL ;
    PORT
      LAYER M4 ;
      RECT 1.000 21.504 3.000 21.528 ;
    END
    PORT
      LAYER M4 ;
      RECT 1.000 21.492 4.000 21.540 ;
    END
  END rd_out[149]
  PIN rd_out[150]
    DIRECTION OUTPUT ;
    USE SIGNAL ;
    PORT
      LAYER M4 ;
      RECT 1.000 21.648 3.000 21.672 ;
    END
    PORT
      LAYER M4 ;
      RECT 1.000 21.636 4.000 21.684 ;
    END
  END rd_out[150]
  PIN rd_out[151]
    DIRECTION OUTPUT ;
    USE SIGNAL ;
    PORT
      LAYER M4 ;
      RECT 1.000 21.792 3.000 21.816 ;
    END
    PORT
      LAYER M4 ;
      RECT 1.000 21.780 4.000 21.828 ;
    END
  END rd_out[151]
  PIN rd_out[152]
    DIRECTION OUTPUT ;
    USE SIGNAL ;
    PORT
      LAYER M4 ;
      RECT 1.000 21.936 3.000 21.960 ;
    END
    PORT
      LAYER M4 ;
      RECT 1.000 21.924 4.000 21.972 ;
    END
  END rd_out[152]
  PIN rd_out[153]
    DIRECTION OUTPUT ;
    USE SIGNAL ;
    PORT
      LAYER M4 ;
      RECT 1.000 22.080 3.000 22.104 ;
    END
    PORT
      LAYER M4 ;
      RECT 1.000 22.068 4.000 22.116 ;
    END
  END rd_out[153]
  PIN rd_out[154]
    DIRECTION OUTPUT ;
    USE SIGNAL ;
    PORT
      LAYER M4 ;
      RECT 1.000 22.224 3.000 22.248 ;
    END
    PORT
      LAYER M4 ;
      RECT 1.000 22.212 4.000 22.260 ;
    END
  END rd_out[154]
  PIN rd_out[155]
    DIRECTION OUTPUT ;
    USE SIGNAL ;
    PORT
      LAYER M4 ;
      RECT 1.000 22.368 3.000 22.392 ;
    END
    PORT
      LAYER M4 ;
      RECT 1.000 22.356 4.000 22.404 ;
    END
  END rd_out[155]
  PIN rd_out[156]
    DIRECTION OUTPUT ;
    USE SIGNAL ;
    PORT
      LAYER M4 ;
      RECT 1.000 22.512 3.000 22.536 ;
    END
    PORT
      LAYER M4 ;
      RECT 1.000 22.500 4.000 22.548 ;
    END
  END rd_out[156]
  PIN rd_out[157]
    DIRECTION OUTPUT ;
    USE SIGNAL ;
    PORT
      LAYER M4 ;
      RECT 1.000 22.656 3.000 22.680 ;
    END
    PORT
      LAYER M4 ;
      RECT 1.000 22.644 4.000 22.692 ;
    END
  END rd_out[157]
  PIN rd_out[158]
    DIRECTION OUTPUT ;
    USE SIGNAL ;
    PORT
      LAYER M4 ;
      RECT 1.000 22.800 3.000 22.824 ;
    END
    PORT
      LAYER M4 ;
      RECT 1.000 22.788 4.000 22.836 ;
    END
  END rd_out[158]
  PIN rd_out[159]
    DIRECTION OUTPUT ;
    USE SIGNAL ;
    PORT
      LAYER M4 ;
      RECT 1.000 22.944 3.000 22.968 ;
    END
    PORT
      LAYER M4 ;
      RECT 1.000 22.932 4.000 22.980 ;
    END
  END rd_out[159]
  PIN rd_out[160]
    DIRECTION OUTPUT ;
    USE SIGNAL ;
    PORT
      LAYER M4 ;
      RECT 1.000 23.088 3.000 23.112 ;
    END
    PORT
      LAYER M4 ;
      RECT 1.000 23.076 4.000 23.124 ;
    END
  END rd_out[160]
  PIN rd_out[161]
    DIRECTION OUTPUT ;
    USE SIGNAL ;
    PORT
      LAYER M4 ;
      RECT 1.000 23.232 3.000 23.256 ;
    END
    PORT
      LAYER M4 ;
      RECT 1.000 23.220 4.000 23.268 ;
    END
  END rd_out[161]
  PIN rd_out[162]
    DIRECTION OUTPUT ;
    USE SIGNAL ;
    PORT
      LAYER M4 ;
      RECT 1.000 23.376 3.000 23.400 ;
    END
    PORT
      LAYER M4 ;
      RECT 1.000 23.364 4.000 23.412 ;
    END
  END rd_out[162]
  PIN rd_out[163]
    DIRECTION OUTPUT ;
    USE SIGNAL ;
    PORT
      LAYER M4 ;
      RECT 1.000 23.520 3.000 23.544 ;
    END
    PORT
      LAYER M4 ;
      RECT 1.000 23.508 4.000 23.556 ;
    END
  END rd_out[163]
  PIN rd_out[164]
    DIRECTION OUTPUT ;
    USE SIGNAL ;
    PORT
      LAYER M4 ;
      RECT 1.000 23.664 3.000 23.688 ;
    END
    PORT
      LAYER M4 ;
      RECT 1.000 23.652 4.000 23.700 ;
    END
  END rd_out[164]
  PIN rd_out[165]
    DIRECTION OUTPUT ;
    USE SIGNAL ;
    PORT
      LAYER M4 ;
      RECT 1.000 23.808 3.000 23.832 ;
    END
    PORT
      LAYER M4 ;
      RECT 1.000 23.796 4.000 23.844 ;
    END
  END rd_out[165]
  PIN rd_out[166]
    DIRECTION OUTPUT ;
    USE SIGNAL ;
    PORT
      LAYER M4 ;
      RECT 1.000 23.952 3.000 23.976 ;
    END
    PORT
      LAYER M4 ;
      RECT 1.000 23.940 4.000 23.988 ;
    END
  END rd_out[166]
  PIN rd_out[167]
    DIRECTION OUTPUT ;
    USE SIGNAL ;
    PORT
      LAYER M4 ;
      RECT 1.000 24.096 3.000 24.120 ;
    END
    PORT
      LAYER M4 ;
      RECT 1.000 24.084 4.000 24.132 ;
    END
  END rd_out[167]
  PIN rd_out[168]
    DIRECTION OUTPUT ;
    USE SIGNAL ;
    PORT
      LAYER M4 ;
      RECT 1.000 24.240 3.000 24.264 ;
    END
    PORT
      LAYER M4 ;
      RECT 1.000 24.228 4.000 24.276 ;
    END
  END rd_out[168]
  PIN rd_out[169]
    DIRECTION OUTPUT ;
    USE SIGNAL ;
    PORT
      LAYER M4 ;
      RECT 1.000 24.384 3.000 24.408 ;
    END
    PORT
      LAYER M4 ;
      RECT 1.000 24.372 4.000 24.420 ;
    END
  END rd_out[169]
  PIN rd_out[170]
    DIRECTION OUTPUT ;
    USE SIGNAL ;
    PORT
      LAYER M4 ;
      RECT 1.000 24.528 3.000 24.552 ;
    END
    PORT
      LAYER M4 ;
      RECT 1.000 24.516 4.000 24.564 ;
    END
  END rd_out[170]
  PIN rd_out[171]
    DIRECTION OUTPUT ;
    USE SIGNAL ;
    PORT
      LAYER M4 ;
      RECT 1.000 24.672 3.000 24.696 ;
    END
    PORT
      LAYER M4 ;
      RECT 1.000 24.660 4.000 24.708 ;
    END
  END rd_out[171]
  PIN rd_out[172]
    DIRECTION OUTPUT ;
    USE SIGNAL ;
    PORT
      LAYER M4 ;
      RECT 1.000 24.816 3.000 24.840 ;
    END
    PORT
      LAYER M4 ;
      RECT 1.000 24.804 4.000 24.852 ;
    END
  END rd_out[172]
  PIN rd_out[173]
    DIRECTION OUTPUT ;
    USE SIGNAL ;
    PORT
      LAYER M4 ;
      RECT 1.000 24.960 3.000 24.984 ;
    END
    PORT
      LAYER M4 ;
      RECT 1.000 24.948 4.000 24.996 ;
    END
  END rd_out[173]
  PIN rd_out[174]
    DIRECTION OUTPUT ;
    USE SIGNAL ;
    PORT
      LAYER M4 ;
      RECT 1.000 25.104 3.000 25.128 ;
    END
    PORT
      LAYER M4 ;
      RECT 1.000 25.092 4.000 25.140 ;
    END
  END rd_out[174]
  PIN rd_out[175]
    DIRECTION OUTPUT ;
    USE SIGNAL ;
    PORT
      LAYER M4 ;
      RECT 1.000 25.248 3.000 25.272 ;
    END
    PORT
      LAYER M4 ;
      RECT 1.000 25.236 4.000 25.284 ;
    END
  END rd_out[175]
  PIN rd_out[176]
    DIRECTION OUTPUT ;
    USE SIGNAL ;
    PORT
      LAYER M4 ;
      RECT 1.000 25.392 3.000 25.416 ;
    END
    PORT
      LAYER M4 ;
      RECT 1.000 25.380 4.000 25.428 ;
    END
  END rd_out[176]
  PIN rd_out[177]
    DIRECTION OUTPUT ;
    USE SIGNAL ;
    PORT
      LAYER M4 ;
      RECT 1.000 25.536 3.000 25.560 ;
    END
    PORT
      LAYER M4 ;
      RECT 1.000 25.524 4.000 25.572 ;
    END
  END rd_out[177]
  PIN rd_out[178]
    DIRECTION OUTPUT ;
    USE SIGNAL ;
    PORT
      LAYER M4 ;
      RECT 1.000 25.680 3.000 25.704 ;
    END
    PORT
      LAYER M4 ;
      RECT 1.000 25.668 4.000 25.716 ;
    END
  END rd_out[178]
  PIN rd_out[179]
    DIRECTION OUTPUT ;
    USE SIGNAL ;
    PORT
      LAYER M4 ;
      RECT 1.000 25.824 3.000 25.848 ;
    END
    PORT
      LAYER M4 ;
      RECT 1.000 25.812 4.000 25.860 ;
    END
  END rd_out[179]
  PIN rd_out[180]
    DIRECTION OUTPUT ;
    USE SIGNAL ;
    PORT
      LAYER M4 ;
      RECT 1.000 25.968 3.000 25.992 ;
    END
    PORT
      LAYER M4 ;
      RECT 1.000 25.956 4.000 26.004 ;
    END
  END rd_out[180]
  PIN rd_out[181]
    DIRECTION OUTPUT ;
    USE SIGNAL ;
    PORT
      LAYER M4 ;
      RECT 1.000 26.112 3.000 26.136 ;
    END
    PORT
      LAYER M4 ;
      RECT 1.000 26.100 4.000 26.148 ;
    END
  END rd_out[181]
  PIN rd_out[182]
    DIRECTION OUTPUT ;
    USE SIGNAL ;
    PORT
      LAYER M4 ;
      RECT 1.000 26.256 3.000 26.280 ;
    END
    PORT
      LAYER M4 ;
      RECT 1.000 26.244 4.000 26.292 ;
    END
  END rd_out[182]
  PIN rd_out[183]
    DIRECTION OUTPUT ;
    USE SIGNAL ;
    PORT
      LAYER M4 ;
      RECT 1.000 26.400 3.000 26.424 ;
    END
    PORT
      LAYER M4 ;
      RECT 1.000 26.388 4.000 26.436 ;
    END
  END rd_out[183]
  PIN rd_out[184]
    DIRECTION OUTPUT ;
    USE SIGNAL ;
    PORT
      LAYER M4 ;
      RECT 1.000 26.544 3.000 26.568 ;
    END
    PORT
      LAYER M4 ;
      RECT 1.000 26.532 4.000 26.580 ;
    END
  END rd_out[184]
  PIN rd_out[185]
    DIRECTION OUTPUT ;
    USE SIGNAL ;
    PORT
      LAYER M4 ;
      RECT 1.000 26.688 3.000 26.712 ;
    END
    PORT
      LAYER M4 ;
      RECT 1.000 26.676 4.000 26.724 ;
    END
  END rd_out[185]
  PIN rd_out[186]
    DIRECTION OUTPUT ;
    USE SIGNAL ;
    PORT
      LAYER M4 ;
      RECT 1.000 26.832 3.000 26.856 ;
    END
    PORT
      LAYER M4 ;
      RECT 1.000 26.820 4.000 26.868 ;
    END
  END rd_out[186]
  PIN rd_out[187]
    DIRECTION OUTPUT ;
    USE SIGNAL ;
    PORT
      LAYER M4 ;
      RECT 1.000 26.976 3.000 27.000 ;
    END
    PORT
      LAYER M4 ;
      RECT 1.000 26.964 4.000 27.012 ;
    END
  END rd_out[187]
  PIN rd_out[188]
    DIRECTION OUTPUT ;
    USE SIGNAL ;
    PORT
      LAYER M4 ;
      RECT 1.000 27.120 3.000 27.144 ;
    END
    PORT
      LAYER M4 ;
      RECT 1.000 27.108 4.000 27.156 ;
    END
  END rd_out[188]
  PIN rd_out[189]
    DIRECTION OUTPUT ;
    USE SIGNAL ;
    PORT
      LAYER M4 ;
      RECT 1.000 27.264 3.000 27.288 ;
    END
    PORT
      LAYER M4 ;
      RECT 1.000 27.252 4.000 27.300 ;
    END
  END rd_out[189]
  PIN rd_out[190]
    DIRECTION OUTPUT ;
    USE SIGNAL ;
    PORT
      LAYER M4 ;
      RECT 1.000 27.408 3.000 27.432 ;
    END
    PORT
      LAYER M4 ;
      RECT 1.000 27.396 4.000 27.444 ;
    END
  END rd_out[190]
  PIN rd_out[191]
    DIRECTION OUTPUT ;
    USE SIGNAL ;
    PORT
      LAYER M4 ;
      RECT 1.000 27.552 3.000 27.576 ;
    END
    PORT
      LAYER M4 ;
      RECT 1.000 27.540 4.000 27.588 ;
    END
  END rd_out[191]
  PIN rd_out[192]
    DIRECTION OUTPUT ;
    USE SIGNAL ;
    PORT
      LAYER M4 ;
      RECT 1.000 27.696 3.000 27.720 ;
    END
    PORT
      LAYER M4 ;
      RECT 1.000 27.684 4.000 27.732 ;
    END
  END rd_out[192]
  PIN rd_out[193]
    DIRECTION OUTPUT ;
    USE SIGNAL ;
    PORT
      LAYER M4 ;
      RECT 1.000 27.840 3.000 27.864 ;
    END
    PORT
      LAYER M4 ;
      RECT 1.000 27.828 4.000 27.876 ;
    END
  END rd_out[193]
  PIN rd_out[194]
    DIRECTION OUTPUT ;
    USE SIGNAL ;
    PORT
      LAYER M4 ;
      RECT 1.000 27.984 3.000 28.008 ;
    END
    PORT
      LAYER M4 ;
      RECT 1.000 27.972 4.000 28.020 ;
    END
  END rd_out[194]
  PIN rd_out[195]
    DIRECTION OUTPUT ;
    USE SIGNAL ;
    PORT
      LAYER M4 ;
      RECT 1.000 28.128 3.000 28.152 ;
    END
    PORT
      LAYER M4 ;
      RECT 1.000 28.116 4.000 28.164 ;
    END
  END rd_out[195]
  PIN rd_out[196]
    DIRECTION OUTPUT ;
    USE SIGNAL ;
    PORT
      LAYER M4 ;
      RECT 1.000 28.272 3.000 28.296 ;
    END
    PORT
      LAYER M4 ;
      RECT 1.000 28.260 4.000 28.308 ;
    END
  END rd_out[196]
  PIN rd_out[197]
    DIRECTION OUTPUT ;
    USE SIGNAL ;
    PORT
      LAYER M4 ;
      RECT 1.000 28.416 3.000 28.440 ;
    END
    PORT
      LAYER M4 ;
      RECT 1.000 28.404 4.000 28.452 ;
    END
  END rd_out[197]
  PIN rd_out[198]
    DIRECTION OUTPUT ;
    USE SIGNAL ;
    PORT
      LAYER M4 ;
      RECT 1.000 28.560 3.000 28.584 ;
    END
    PORT
      LAYER M4 ;
      RECT 1.000 28.548 4.000 28.596 ;
    END
  END rd_out[198]
  PIN rd_out[199]
    DIRECTION OUTPUT ;
    USE SIGNAL ;
    PORT
      LAYER M4 ;
      RECT 1.000 28.704 3.000 28.728 ;
    END
    PORT
      LAYER M4 ;
      RECT 1.000 28.692 4.000 28.740 ;
    END
  END rd_out[199]
  PIN rd_out[200]
    DIRECTION OUTPUT ;
    USE SIGNAL ;
    PORT
      LAYER M4 ;
      RECT 1.000 28.848 3.000 28.872 ;
    END
    PORT
      LAYER M4 ;
      RECT 1.000 28.836 4.000 28.884 ;
    END
  END rd_out[200]
  PIN rd_out[201]
    DIRECTION OUTPUT ;
    USE SIGNAL ;
    PORT
      LAYER M4 ;
      RECT 1.000 28.992 3.000 29.016 ;
    END
    PORT
      LAYER M4 ;
      RECT 1.000 28.980 4.000 29.028 ;
    END
  END rd_out[201]
  PIN rd_out[202]
    DIRECTION OUTPUT ;
    USE SIGNAL ;
    PORT
      LAYER M4 ;
      RECT 1.000 29.136 3.000 29.160 ;
    END
    PORT
      LAYER M4 ;
      RECT 1.000 29.124 4.000 29.172 ;
    END
  END rd_out[202]
  PIN rd_out[203]
    DIRECTION OUTPUT ;
    USE SIGNAL ;
    PORT
      LAYER M4 ;
      RECT 1.000 29.280 3.000 29.304 ;
    END
    PORT
      LAYER M4 ;
      RECT 1.000 29.268 4.000 29.316 ;
    END
  END rd_out[203]
  PIN rd_out[204]
    DIRECTION OUTPUT ;
    USE SIGNAL ;
    PORT
      LAYER M4 ;
      RECT 1.000 29.424 3.000 29.448 ;
    END
    PORT
      LAYER M4 ;
      RECT 1.000 29.412 4.000 29.460 ;
    END
  END rd_out[204]
  PIN rd_out[205]
    DIRECTION OUTPUT ;
    USE SIGNAL ;
    PORT
      LAYER M4 ;
      RECT 1.000 29.568 3.000 29.592 ;
    END
    PORT
      LAYER M4 ;
      RECT 1.000 29.556 4.000 29.604 ;
    END
  END rd_out[205]
  PIN rd_out[206]
    DIRECTION OUTPUT ;
    USE SIGNAL ;
    PORT
      LAYER M4 ;
      RECT 1.000 29.712 3.000 29.736 ;
    END
    PORT
      LAYER M4 ;
      RECT 1.000 29.700 4.000 29.748 ;
    END
  END rd_out[206]
  PIN rd_out[207]
    DIRECTION OUTPUT ;
    USE SIGNAL ;
    PORT
      LAYER M4 ;
      RECT 1.000 29.856 3.000 29.880 ;
    END
    PORT
      LAYER M4 ;
      RECT 1.000 29.844 4.000 29.892 ;
    END
  END rd_out[207]
  PIN rd_out[208]
    DIRECTION OUTPUT ;
    USE SIGNAL ;
    PORT
      LAYER M4 ;
      RECT 1.000 30.000 3.000 30.024 ;
    END
    PORT
      LAYER M4 ;
      RECT 1.000 29.988 4.000 30.036 ;
    END
  END rd_out[208]
  PIN rd_out[209]
    DIRECTION OUTPUT ;
    USE SIGNAL ;
    PORT
      LAYER M4 ;
      RECT 1.000 30.144 3.000 30.168 ;
    END
    PORT
      LAYER M4 ;
      RECT 1.000 30.132 4.000 30.180 ;
    END
  END rd_out[209]
  PIN rd_out[210]
    DIRECTION OUTPUT ;
    USE SIGNAL ;
    PORT
      LAYER M4 ;
      RECT 1.000 30.288 3.000 30.312 ;
    END
    PORT
      LAYER M4 ;
      RECT 1.000 30.276 4.000 30.324 ;
    END
  END rd_out[210]
  PIN rd_out[211]
    DIRECTION OUTPUT ;
    USE SIGNAL ;
    PORT
      LAYER M4 ;
      RECT 1.000 30.432 3.000 30.456 ;
    END
    PORT
      LAYER M4 ;
      RECT 1.000 30.420 4.000 30.468 ;
    END
  END rd_out[211]
  PIN rd_out[212]
    DIRECTION OUTPUT ;
    USE SIGNAL ;
    PORT
      LAYER M4 ;
      RECT 1.000 30.576 3.000 30.600 ;
    END
    PORT
      LAYER M4 ;
      RECT 1.000 30.564 4.000 30.612 ;
    END
  END rd_out[212]
  PIN rd_out[213]
    DIRECTION OUTPUT ;
    USE SIGNAL ;
    PORT
      LAYER M4 ;
      RECT 1.000 30.720 3.000 30.744 ;
    END
    PORT
      LAYER M4 ;
      RECT 1.000 30.708 4.000 30.756 ;
    END
  END rd_out[213]
  PIN rd_out[214]
    DIRECTION OUTPUT ;
    USE SIGNAL ;
    PORT
      LAYER M4 ;
      RECT 1.000 30.864 3.000 30.888 ;
    END
    PORT
      LAYER M4 ;
      RECT 1.000 30.852 4.000 30.900 ;
    END
  END rd_out[214]
  PIN rd_out[215]
    DIRECTION OUTPUT ;
    USE SIGNAL ;
    PORT
      LAYER M4 ;
      RECT 1.000 31.008 3.000 31.032 ;
    END
    PORT
      LAYER M4 ;
      RECT 1.000 30.996 4.000 31.044 ;
    END
  END rd_out[215]
  PIN rd_out[216]
    DIRECTION OUTPUT ;
    USE SIGNAL ;
    PORT
      LAYER M4 ;
      RECT 1.000 31.152 3.000 31.176 ;
    END
    PORT
      LAYER M4 ;
      RECT 1.000 31.140 4.000 31.188 ;
    END
  END rd_out[216]
  PIN rd_out[217]
    DIRECTION OUTPUT ;
    USE SIGNAL ;
    PORT
      LAYER M4 ;
      RECT 1.000 31.296 3.000 31.320 ;
    END
    PORT
      LAYER M4 ;
      RECT 1.000 31.284 4.000 31.332 ;
    END
  END rd_out[217]
  PIN rd_out[218]
    DIRECTION OUTPUT ;
    USE SIGNAL ;
    PORT
      LAYER M4 ;
      RECT 1.000 31.440 3.000 31.464 ;
    END
    PORT
      LAYER M4 ;
      RECT 1.000 31.428 4.000 31.476 ;
    END
  END rd_out[218]
  PIN rd_out[219]
    DIRECTION OUTPUT ;
    USE SIGNAL ;
    PORT
      LAYER M4 ;
      RECT 1.000 31.584 3.000 31.608 ;
    END
    PORT
      LAYER M4 ;
      RECT 1.000 31.572 4.000 31.620 ;
    END
  END rd_out[219]
  PIN rd_out[220]
    DIRECTION OUTPUT ;
    USE SIGNAL ;
    PORT
      LAYER M4 ;
      RECT 1.000 31.728 3.000 31.752 ;
    END
    PORT
      LAYER M4 ;
      RECT 1.000 31.716 4.000 31.764 ;
    END
  END rd_out[220]
  PIN rd_out[221]
    DIRECTION OUTPUT ;
    USE SIGNAL ;
    PORT
      LAYER M4 ;
      RECT 1.000 31.872 3.000 31.896 ;
    END
    PORT
      LAYER M4 ;
      RECT 1.000 31.860 4.000 31.908 ;
    END
  END rd_out[221]
  PIN rd_out[222]
    DIRECTION OUTPUT ;
    USE SIGNAL ;
    PORT
      LAYER M4 ;
      RECT 1.000 32.016 3.000 32.040 ;
    END
    PORT
      LAYER M4 ;
      RECT 1.000 32.004 4.000 32.052 ;
    END
  END rd_out[222]
  PIN rd_out[223]
    DIRECTION OUTPUT ;
    USE SIGNAL ;
    PORT
      LAYER M4 ;
      RECT 1.000 32.160 3.000 32.184 ;
    END
    PORT
      LAYER M4 ;
      RECT 1.000 32.148 4.000 32.196 ;
    END
  END rd_out[223]
  PIN rd_out[224]
    DIRECTION OUTPUT ;
    USE SIGNAL ;
    PORT
      LAYER M4 ;
      RECT 1.000 32.304 3.000 32.328 ;
    END
    PORT
      LAYER M4 ;
      RECT 1.000 32.292 4.000 32.340 ;
    END
  END rd_out[224]
  PIN rd_out[225]
    DIRECTION OUTPUT ;
    USE SIGNAL ;
    PORT
      LAYER M4 ;
      RECT 1.000 32.448 3.000 32.472 ;
    END
    PORT
      LAYER M4 ;
      RECT 1.000 32.436 4.000 32.484 ;
    END
  END rd_out[225]
  PIN rd_out[226]
    DIRECTION OUTPUT ;
    USE SIGNAL ;
    PORT
      LAYER M4 ;
      RECT 1.000 32.592 3.000 32.616 ;
    END
    PORT
      LAYER M4 ;
      RECT 1.000 32.580 4.000 32.628 ;
    END
  END rd_out[226]
  PIN rd_out[227]
    DIRECTION OUTPUT ;
    USE SIGNAL ;
    PORT
      LAYER M4 ;
      RECT 1.000 32.736 3.000 32.760 ;
    END
    PORT
      LAYER M4 ;
      RECT 1.000 32.724 4.000 32.772 ;
    END
  END rd_out[227]
  PIN rd_out[228]
    DIRECTION OUTPUT ;
    USE SIGNAL ;
    PORT
      LAYER M4 ;
      RECT 1.000 32.880 3.000 32.904 ;
    END
    PORT
      LAYER M4 ;
      RECT 1.000 32.868 4.000 32.916 ;
    END
  END rd_out[228]
  PIN rd_out[229]
    DIRECTION OUTPUT ;
    USE SIGNAL ;
    PORT
      LAYER M4 ;
      RECT 1.000 33.024 3.000 33.048 ;
    END
    PORT
      LAYER M4 ;
      RECT 1.000 33.012 4.000 33.060 ;
    END
  END rd_out[229]
  PIN rd_out[230]
    DIRECTION OUTPUT ;
    USE SIGNAL ;
    PORT
      LAYER M4 ;
      RECT 1.000 33.168 3.000 33.192 ;
    END
    PORT
      LAYER M4 ;
      RECT 1.000 33.156 4.000 33.204 ;
    END
  END rd_out[230]
  PIN rd_out[231]
    DIRECTION OUTPUT ;
    USE SIGNAL ;
    PORT
      LAYER M4 ;
      RECT 1.000 33.312 3.000 33.336 ;
    END
    PORT
      LAYER M4 ;
      RECT 1.000 33.300 4.000 33.348 ;
    END
  END rd_out[231]
  PIN rd_out[232]
    DIRECTION OUTPUT ;
    USE SIGNAL ;
    PORT
      LAYER M4 ;
      RECT 1.000 33.456 3.000 33.480 ;
    END
    PORT
      LAYER M4 ;
      RECT 1.000 33.444 4.000 33.492 ;
    END
  END rd_out[232]
  PIN rd_out[233]
    DIRECTION OUTPUT ;
    USE SIGNAL ;
    PORT
      LAYER M4 ;
      RECT 1.000 33.600 3.000 33.624 ;
    END
    PORT
      LAYER M4 ;
      RECT 1.000 33.588 4.000 33.636 ;
    END
  END rd_out[233]
  PIN rd_out[234]
    DIRECTION OUTPUT ;
    USE SIGNAL ;
    PORT
      LAYER M4 ;
      RECT 1.000 33.744 3.000 33.768 ;
    END
    PORT
      LAYER M4 ;
      RECT 1.000 33.732 4.000 33.780 ;
    END
  END rd_out[234]
  PIN rd_out[235]
    DIRECTION OUTPUT ;
    USE SIGNAL ;
    PORT
      LAYER M4 ;
      RECT 1.000 33.888 3.000 33.912 ;
    END
    PORT
      LAYER M4 ;
      RECT 1.000 33.876 4.000 33.924 ;
    END
  END rd_out[235]
  PIN rd_out[236]
    DIRECTION OUTPUT ;
    USE SIGNAL ;
    PORT
      LAYER M4 ;
      RECT 1.000 34.032 3.000 34.056 ;
    END
    PORT
      LAYER M4 ;
      RECT 1.000 34.020 4.000 34.068 ;
    END
  END rd_out[236]
  PIN rd_out[237]
    DIRECTION OUTPUT ;
    USE SIGNAL ;
    PORT
      LAYER M4 ;
      RECT 1.000 34.176 3.000 34.200 ;
    END
    PORT
      LAYER M4 ;
      RECT 1.000 34.164 4.000 34.212 ;
    END
  END rd_out[237]
  PIN rd_out[238]
    DIRECTION OUTPUT ;
    USE SIGNAL ;
    PORT
      LAYER M4 ;
      RECT 1.000 34.320 3.000 34.344 ;
    END
    PORT
      LAYER M4 ;
      RECT 1.000 34.308 4.000 34.356 ;
    END
  END rd_out[238]
  PIN rd_out[239]
    DIRECTION OUTPUT ;
    USE SIGNAL ;
    PORT
      LAYER M4 ;
      RECT 1.000 34.464 3.000 34.488 ;
    END
    PORT
      LAYER M4 ;
      RECT 1.000 34.452 4.000 34.500 ;
    END
  END rd_out[239]
  PIN rd_out[240]
    DIRECTION OUTPUT ;
    USE SIGNAL ;
    PORT
      LAYER M4 ;
      RECT 1.000 34.608 3.000 34.632 ;
    END
    PORT
      LAYER M4 ;
      RECT 1.000 34.596 4.000 34.644 ;
    END
  END rd_out[240]
  PIN rd_out[241]
    DIRECTION OUTPUT ;
    USE SIGNAL ;
    PORT
      LAYER M4 ;
      RECT 1.000 34.752 3.000 34.776 ;
    END
    PORT
      LAYER M4 ;
      RECT 1.000 34.740 4.000 34.788 ;
    END
  END rd_out[241]
  PIN rd_out[242]
    DIRECTION OUTPUT ;
    USE SIGNAL ;
    PORT
      LAYER M4 ;
      RECT 1.000 34.896 3.000 34.920 ;
    END
    PORT
      LAYER M4 ;
      RECT 1.000 34.884 4.000 34.932 ;
    END
  END rd_out[242]
  PIN rd_out[243]
    DIRECTION OUTPUT ;
    USE SIGNAL ;
    PORT
      LAYER M4 ;
      RECT 1.000 35.040 3.000 35.064 ;
    END
    PORT
      LAYER M4 ;
      RECT 1.000 35.028 4.000 35.076 ;
    END
  END rd_out[243]
  PIN rd_out[244]
    DIRECTION OUTPUT ;
    USE SIGNAL ;
    PORT
      LAYER M4 ;
      RECT 1.000 35.184 3.000 35.208 ;
    END
    PORT
      LAYER M4 ;
      RECT 1.000 35.172 4.000 35.220 ;
    END
  END rd_out[244]
  PIN rd_out[245]
    DIRECTION OUTPUT ;
    USE SIGNAL ;
    PORT
      LAYER M4 ;
      RECT 1.000 35.328 3.000 35.352 ;
    END
    PORT
      LAYER M4 ;
      RECT 1.000 35.316 4.000 35.364 ;
    END
  END rd_out[245]
  PIN rd_out[246]
    DIRECTION OUTPUT ;
    USE SIGNAL ;
    PORT
      LAYER M4 ;
      RECT 1.000 35.472 3.000 35.496 ;
    END
    PORT
      LAYER M4 ;
      RECT 1.000 35.460 4.000 35.508 ;
    END
  END rd_out[246]
  PIN rd_out[247]
    DIRECTION OUTPUT ;
    USE SIGNAL ;
    PORT
      LAYER M4 ;
      RECT 1.000 35.616 3.000 35.640 ;
    END
    PORT
      LAYER M4 ;
      RECT 1.000 35.604 4.000 35.652 ;
    END
  END rd_out[247]
  PIN rd_out[248]
    DIRECTION OUTPUT ;
    USE SIGNAL ;
    PORT
      LAYER M4 ;
      RECT 1.000 35.760 3.000 35.784 ;
    END
    PORT
      LAYER M4 ;
      RECT 1.000 35.748 4.000 35.796 ;
    END
  END rd_out[248]
  PIN rd_out[249]
    DIRECTION OUTPUT ;
    USE SIGNAL ;
    PORT
      LAYER M4 ;
      RECT 1.000 35.904 3.000 35.928 ;
    END
    PORT
      LAYER M4 ;
      RECT 1.000 35.892 4.000 35.940 ;
    END
  END rd_out[249]
  PIN rd_out[250]
    DIRECTION OUTPUT ;
    USE SIGNAL ;
    PORT
      LAYER M4 ;
      RECT 1.000 36.048 3.000 36.072 ;
    END
    PORT
      LAYER M4 ;
      RECT 1.000 36.036 4.000 36.084 ;
    END
  END rd_out[250]
  PIN rd_out[251]
    DIRECTION OUTPUT ;
    USE SIGNAL ;
    PORT
      LAYER M4 ;
      RECT 1.000 36.192 3.000 36.216 ;
    END
    PORT
      LAYER M4 ;
      RECT 1.000 36.180 4.000 36.228 ;
    END
  END rd_out[251]
  PIN rd_out[252]
    DIRECTION OUTPUT ;
    USE SIGNAL ;
    PORT
      LAYER M4 ;
      RECT 1.000 36.336 3.000 36.360 ;
    END
    PORT
      LAYER M4 ;
      RECT 1.000 36.324 4.000 36.372 ;
    END
  END rd_out[252]
  PIN rd_out[253]
    DIRECTION OUTPUT ;
    USE SIGNAL ;
    PORT
      LAYER M4 ;
      RECT 1.000 36.480 3.000 36.504 ;
    END
    PORT
      LAYER M4 ;
      RECT 1.000 36.468 4.000 36.516 ;
    END
  END rd_out[253]
  PIN rd_out[254]
    DIRECTION OUTPUT ;
    USE SIGNAL ;
    PORT
      LAYER M4 ;
      RECT 1.000 36.624 3.000 36.648 ;
    END
    PORT
      LAYER M4 ;
      RECT 1.000 36.612 4.000 36.660 ;
    END
  END rd_out[254]
  PIN rd_out[255]
    DIRECTION OUTPUT ;
    USE SIGNAL ;
    PORT
      LAYER M4 ;
      RECT 1.000 36.768 3.000 36.792 ;
    END
    PORT
      LAYER M4 ;
      RECT 1.000 36.756 4.000 36.804 ;
    END
  END rd_out[255]
  PIN wd_in[0]
    DIRECTION INPUT ;
    USE SIGNAL ;
    PORT
      LAYER M4 ;
      RECT 1.000 39.696 3.000 39.720 ;
    END
    PORT
      LAYER M4 ;
      RECT 1.000 39.684 4.000 39.732 ;
    END
  END wd_in[0]
  PIN wd_in[1]
    DIRECTION INPUT ;
    USE SIGNAL ;
    PORT
      LAYER M4 ;
      RECT 1.000 39.840 3.000 39.864 ;
    END
    PORT
      LAYER M4 ;
      RECT 1.000 39.828 4.000 39.876 ;
    END
  END wd_in[1]
  PIN wd_in[2]
    DIRECTION INPUT ;
    USE SIGNAL ;
    PORT
      LAYER M4 ;
      RECT 1.000 39.984 3.000 40.008 ;
    END
    PORT
      LAYER M4 ;
      RECT 1.000 39.972 4.000 40.020 ;
    END
  END wd_in[2]
  PIN wd_in[3]
    DIRECTION INPUT ;
    USE SIGNAL ;
    PORT
      LAYER M4 ;
      RECT 1.000 40.128 3.000 40.152 ;
    END
    PORT
      LAYER M4 ;
      RECT 1.000 40.116 4.000 40.164 ;
    END
  END wd_in[3]
  PIN wd_in[4]
    DIRECTION INPUT ;
    USE SIGNAL ;
    PORT
      LAYER M4 ;
      RECT 1.000 40.272 3.000 40.296 ;
    END
    PORT
      LAYER M4 ;
      RECT 1.000 40.260 4.000 40.308 ;
    END
  END wd_in[4]
  PIN wd_in[5]
    DIRECTION INPUT ;
    USE SIGNAL ;
    PORT
      LAYER M4 ;
      RECT 1.000 40.416 3.000 40.440 ;
    END
    PORT
      LAYER M4 ;
      RECT 1.000 40.404 4.000 40.452 ;
    END
  END wd_in[5]
  PIN wd_in[6]
    DIRECTION INPUT ;
    USE SIGNAL ;
    PORT
      LAYER M4 ;
      RECT 1.000 40.560 3.000 40.584 ;
    END
    PORT
      LAYER M4 ;
      RECT 1.000 40.548 4.000 40.596 ;
    END
  END wd_in[6]
  PIN wd_in[7]
    DIRECTION INPUT ;
    USE SIGNAL ;
    PORT
      LAYER M4 ;
      RECT 1.000 40.704 3.000 40.728 ;
    END
    PORT
      LAYER M4 ;
      RECT 1.000 40.692 4.000 40.740 ;
    END
  END wd_in[7]
  PIN wd_in[8]
    DIRECTION INPUT ;
    USE SIGNAL ;
    PORT
      LAYER M4 ;
      RECT 1.000 40.848 3.000 40.872 ;
    END
    PORT
      LAYER M4 ;
      RECT 1.000 40.836 4.000 40.884 ;
    END
  END wd_in[8]
  PIN wd_in[9]
    DIRECTION INPUT ;
    USE SIGNAL ;
    PORT
      LAYER M4 ;
      RECT 1.000 40.992 3.000 41.016 ;
    END
    PORT
      LAYER M4 ;
      RECT 1.000 40.980 4.000 41.028 ;
    END
  END wd_in[9]
  PIN wd_in[10]
    DIRECTION INPUT ;
    USE SIGNAL ;
    PORT
      LAYER M4 ;
      RECT 1.000 41.136 3.000 41.160 ;
    END
    PORT
      LAYER M4 ;
      RECT 1.000 41.124 4.000 41.172 ;
    END
  END wd_in[10]
  PIN wd_in[11]
    DIRECTION INPUT ;
    USE SIGNAL ;
    PORT
      LAYER M4 ;
      RECT 1.000 41.280 3.000 41.304 ;
    END
    PORT
      LAYER M4 ;
      RECT 1.000 41.268 4.000 41.316 ;
    END
  END wd_in[11]
  PIN wd_in[12]
    DIRECTION INPUT ;
    USE SIGNAL ;
    PORT
      LAYER M4 ;
      RECT 1.000 41.424 3.000 41.448 ;
    END
    PORT
      LAYER M4 ;
      RECT 1.000 41.412 4.000 41.460 ;
    END
  END wd_in[12]
  PIN wd_in[13]
    DIRECTION INPUT ;
    USE SIGNAL ;
    PORT
      LAYER M4 ;
      RECT 1.000 41.568 3.000 41.592 ;
    END
    PORT
      LAYER M4 ;
      RECT 1.000 41.556 4.000 41.604 ;
    END
  END wd_in[13]
  PIN wd_in[14]
    DIRECTION INPUT ;
    USE SIGNAL ;
    PORT
      LAYER M4 ;
      RECT 1.000 41.712 3.000 41.736 ;
    END
    PORT
      LAYER M4 ;
      RECT 1.000 41.700 4.000 41.748 ;
    END
  END wd_in[14]
  PIN wd_in[15]
    DIRECTION INPUT ;
    USE SIGNAL ;
    PORT
      LAYER M4 ;
      RECT 1.000 41.856 3.000 41.880 ;
    END
    PORT
      LAYER M4 ;
      RECT 1.000 41.844 4.000 41.892 ;
    END
  END wd_in[15]
  PIN wd_in[16]
    DIRECTION INPUT ;
    USE SIGNAL ;
    PORT
      LAYER M4 ;
      RECT 1.000 42.000 3.000 42.024 ;
    END
    PORT
      LAYER M4 ;
      RECT 1.000 41.988 4.000 42.036 ;
    END
  END wd_in[16]
  PIN wd_in[17]
    DIRECTION INPUT ;
    USE SIGNAL ;
    PORT
      LAYER M4 ;
      RECT 1.000 42.144 3.000 42.168 ;
    END
    PORT
      LAYER M4 ;
      RECT 1.000 42.132 4.000 42.180 ;
    END
  END wd_in[17]
  PIN wd_in[18]
    DIRECTION INPUT ;
    USE SIGNAL ;
    PORT
      LAYER M4 ;
      RECT 1.000 42.288 3.000 42.312 ;
    END
    PORT
      LAYER M4 ;
      RECT 1.000 42.276 4.000 42.324 ;
    END
  END wd_in[18]
  PIN wd_in[19]
    DIRECTION INPUT ;
    USE SIGNAL ;
    PORT
      LAYER M4 ;
      RECT 1.000 42.432 3.000 42.456 ;
    END
    PORT
      LAYER M4 ;
      RECT 1.000 42.420 4.000 42.468 ;
    END
  END wd_in[19]
  PIN wd_in[20]
    DIRECTION INPUT ;
    USE SIGNAL ;
    PORT
      LAYER M4 ;
      RECT 1.000 42.576 3.000 42.600 ;
    END
    PORT
      LAYER M4 ;
      RECT 1.000 42.564 4.000 42.612 ;
    END
  END wd_in[20]
  PIN wd_in[21]
    DIRECTION INPUT ;
    USE SIGNAL ;
    PORT
      LAYER M4 ;
      RECT 1.000 42.720 3.000 42.744 ;
    END
    PORT
      LAYER M4 ;
      RECT 1.000 42.708 4.000 42.756 ;
    END
  END wd_in[21]
  PIN wd_in[22]
    DIRECTION INPUT ;
    USE SIGNAL ;
    PORT
      LAYER M4 ;
      RECT 1.000 42.864 3.000 42.888 ;
    END
    PORT
      LAYER M4 ;
      RECT 1.000 42.852 4.000 42.900 ;
    END
  END wd_in[22]
  PIN wd_in[23]
    DIRECTION INPUT ;
    USE SIGNAL ;
    PORT
      LAYER M4 ;
      RECT 1.000 43.008 3.000 43.032 ;
    END
    PORT
      LAYER M4 ;
      RECT 1.000 42.996 4.000 43.044 ;
    END
  END wd_in[23]
  PIN wd_in[24]
    DIRECTION INPUT ;
    USE SIGNAL ;
    PORT
      LAYER M4 ;
      RECT 1.000 43.152 3.000 43.176 ;
    END
    PORT
      LAYER M4 ;
      RECT 1.000 43.140 4.000 43.188 ;
    END
  END wd_in[24]
  PIN wd_in[25]
    DIRECTION INPUT ;
    USE SIGNAL ;
    PORT
      LAYER M4 ;
      RECT 1.000 43.296 3.000 43.320 ;
    END
    PORT
      LAYER M4 ;
      RECT 1.000 43.284 4.000 43.332 ;
    END
  END wd_in[25]
  PIN wd_in[26]
    DIRECTION INPUT ;
    USE SIGNAL ;
    PORT
      LAYER M4 ;
      RECT 1.000 43.440 3.000 43.464 ;
    END
    PORT
      LAYER M4 ;
      RECT 1.000 43.428 4.000 43.476 ;
    END
  END wd_in[26]
  PIN wd_in[27]
    DIRECTION INPUT ;
    USE SIGNAL ;
    PORT
      LAYER M4 ;
      RECT 1.000 43.584 3.000 43.608 ;
    END
    PORT
      LAYER M4 ;
      RECT 1.000 43.572 4.000 43.620 ;
    END
  END wd_in[27]
  PIN wd_in[28]
    DIRECTION INPUT ;
    USE SIGNAL ;
    PORT
      LAYER M4 ;
      RECT 1.000 43.728 3.000 43.752 ;
    END
    PORT
      LAYER M4 ;
      RECT 1.000 43.716 4.000 43.764 ;
    END
  END wd_in[28]
  PIN wd_in[29]
    DIRECTION INPUT ;
    USE SIGNAL ;
    PORT
      LAYER M4 ;
      RECT 1.000 43.872 3.000 43.896 ;
    END
    PORT
      LAYER M4 ;
      RECT 1.000 43.860 4.000 43.908 ;
    END
  END wd_in[29]
  PIN wd_in[30]
    DIRECTION INPUT ;
    USE SIGNAL ;
    PORT
      LAYER M4 ;
      RECT 1.000 44.016 3.000 44.040 ;
    END
    PORT
      LAYER M4 ;
      RECT 1.000 44.004 4.000 44.052 ;
    END
  END wd_in[30]
  PIN wd_in[31]
    DIRECTION INPUT ;
    USE SIGNAL ;
    PORT
      LAYER M4 ;
      RECT 1.000 44.160 3.000 44.184 ;
    END
    PORT
      LAYER M4 ;
      RECT 1.000 44.148 4.000 44.196 ;
    END
  END wd_in[31]
  PIN wd_in[32]
    DIRECTION INPUT ;
    USE SIGNAL ;
    PORT
      LAYER M4 ;
      RECT 1.000 44.304 3.000 44.328 ;
    END
    PORT
      LAYER M4 ;
      RECT 1.000 44.292 4.000 44.340 ;
    END
  END wd_in[32]
  PIN wd_in[33]
    DIRECTION INPUT ;
    USE SIGNAL ;
    PORT
      LAYER M4 ;
      RECT 1.000 44.448 3.000 44.472 ;
    END
    PORT
      LAYER M4 ;
      RECT 1.000 44.436 4.000 44.484 ;
    END
  END wd_in[33]
  PIN wd_in[34]
    DIRECTION INPUT ;
    USE SIGNAL ;
    PORT
      LAYER M4 ;
      RECT 1.000 44.592 3.000 44.616 ;
    END
    PORT
      LAYER M4 ;
      RECT 1.000 44.580 4.000 44.628 ;
    END
  END wd_in[34]
  PIN wd_in[35]
    DIRECTION INPUT ;
    USE SIGNAL ;
    PORT
      LAYER M4 ;
      RECT 1.000 44.736 3.000 44.760 ;
    END
    PORT
      LAYER M4 ;
      RECT 1.000 44.724 4.000 44.772 ;
    END
  END wd_in[35]
  PIN wd_in[36]
    DIRECTION INPUT ;
    USE SIGNAL ;
    PORT
      LAYER M4 ;
      RECT 1.000 44.880 3.000 44.904 ;
    END
    PORT
      LAYER M4 ;
      RECT 1.000 44.868 4.000 44.916 ;
    END
  END wd_in[36]
  PIN wd_in[37]
    DIRECTION INPUT ;
    USE SIGNAL ;
    PORT
      LAYER M4 ;
      RECT 1.000 45.024 3.000 45.048 ;
    END
    PORT
      LAYER M4 ;
      RECT 1.000 45.012 4.000 45.060 ;
    END
  END wd_in[37]
  PIN wd_in[38]
    DIRECTION INPUT ;
    USE SIGNAL ;
    PORT
      LAYER M4 ;
      RECT 1.000 45.168 3.000 45.192 ;
    END
    PORT
      LAYER M4 ;
      RECT 1.000 45.156 4.000 45.204 ;
    END
  END wd_in[38]
  PIN wd_in[39]
    DIRECTION INPUT ;
    USE SIGNAL ;
    PORT
      LAYER M4 ;
      RECT 1.000 45.312 3.000 45.336 ;
    END
    PORT
      LAYER M4 ;
      RECT 1.000 45.300 4.000 45.348 ;
    END
  END wd_in[39]
  PIN wd_in[40]
    DIRECTION INPUT ;
    USE SIGNAL ;
    PORT
      LAYER M4 ;
      RECT 1.000 45.456 3.000 45.480 ;
    END
    PORT
      LAYER M4 ;
      RECT 1.000 45.444 4.000 45.492 ;
    END
  END wd_in[40]
  PIN wd_in[41]
    DIRECTION INPUT ;
    USE SIGNAL ;
    PORT
      LAYER M4 ;
      RECT 1.000 45.600 3.000 45.624 ;
    END
    PORT
      LAYER M4 ;
      RECT 1.000 45.588 4.000 45.636 ;
    END
  END wd_in[41]
  PIN wd_in[42]
    DIRECTION INPUT ;
    USE SIGNAL ;
    PORT
      LAYER M4 ;
      RECT 1.000 45.744 3.000 45.768 ;
    END
    PORT
      LAYER M4 ;
      RECT 1.000 45.732 4.000 45.780 ;
    END
  END wd_in[42]
  PIN wd_in[43]
    DIRECTION INPUT ;
    USE SIGNAL ;
    PORT
      LAYER M4 ;
      RECT 1.000 45.888 3.000 45.912 ;
    END
    PORT
      LAYER M4 ;
      RECT 1.000 45.876 4.000 45.924 ;
    END
  END wd_in[43]
  PIN wd_in[44]
    DIRECTION INPUT ;
    USE SIGNAL ;
    PORT
      LAYER M4 ;
      RECT 1.000 46.032 3.000 46.056 ;
    END
    PORT
      LAYER M4 ;
      RECT 1.000 46.020 4.000 46.068 ;
    END
  END wd_in[44]
  PIN wd_in[45]
    DIRECTION INPUT ;
    USE SIGNAL ;
    PORT
      LAYER M4 ;
      RECT 1.000 46.176 3.000 46.200 ;
    END
    PORT
      LAYER M4 ;
      RECT 1.000 46.164 4.000 46.212 ;
    END
  END wd_in[45]
  PIN wd_in[46]
    DIRECTION INPUT ;
    USE SIGNAL ;
    PORT
      LAYER M4 ;
      RECT 1.000 46.320 3.000 46.344 ;
    END
    PORT
      LAYER M4 ;
      RECT 1.000 46.308 4.000 46.356 ;
    END
  END wd_in[46]
  PIN wd_in[47]
    DIRECTION INPUT ;
    USE SIGNAL ;
    PORT
      LAYER M4 ;
      RECT 1.000 46.464 3.000 46.488 ;
    END
    PORT
      LAYER M4 ;
      RECT 1.000 46.452 4.000 46.500 ;
    END
  END wd_in[47]
  PIN wd_in[48]
    DIRECTION INPUT ;
    USE SIGNAL ;
    PORT
      LAYER M4 ;
      RECT 1.000 46.608 3.000 46.632 ;
    END
    PORT
      LAYER M4 ;
      RECT 1.000 46.596 4.000 46.644 ;
    END
  END wd_in[48]
  PIN wd_in[49]
    DIRECTION INPUT ;
    USE SIGNAL ;
    PORT
      LAYER M4 ;
      RECT 1.000 46.752 3.000 46.776 ;
    END
    PORT
      LAYER M4 ;
      RECT 1.000 46.740 4.000 46.788 ;
    END
  END wd_in[49]
  PIN wd_in[50]
    DIRECTION INPUT ;
    USE SIGNAL ;
    PORT
      LAYER M4 ;
      RECT 1.000 46.896 3.000 46.920 ;
    END
    PORT
      LAYER M4 ;
      RECT 1.000 46.884 4.000 46.932 ;
    END
  END wd_in[50]
  PIN wd_in[51]
    DIRECTION INPUT ;
    USE SIGNAL ;
    PORT
      LAYER M4 ;
      RECT 1.000 47.040 3.000 47.064 ;
    END
    PORT
      LAYER M4 ;
      RECT 1.000 47.028 4.000 47.076 ;
    END
  END wd_in[51]
  PIN wd_in[52]
    DIRECTION INPUT ;
    USE SIGNAL ;
    PORT
      LAYER M4 ;
      RECT 1.000 47.184 3.000 47.208 ;
    END
    PORT
      LAYER M4 ;
      RECT 1.000 47.172 4.000 47.220 ;
    END
  END wd_in[52]
  PIN wd_in[53]
    DIRECTION INPUT ;
    USE SIGNAL ;
    PORT
      LAYER M4 ;
      RECT 1.000 47.328 3.000 47.352 ;
    END
    PORT
      LAYER M4 ;
      RECT 1.000 47.316 4.000 47.364 ;
    END
  END wd_in[53]
  PIN wd_in[54]
    DIRECTION INPUT ;
    USE SIGNAL ;
    PORT
      LAYER M4 ;
      RECT 1.000 47.472 3.000 47.496 ;
    END
    PORT
      LAYER M4 ;
      RECT 1.000 47.460 4.000 47.508 ;
    END
  END wd_in[54]
  PIN wd_in[55]
    DIRECTION INPUT ;
    USE SIGNAL ;
    PORT
      LAYER M4 ;
      RECT 1.000 47.616 3.000 47.640 ;
    END
    PORT
      LAYER M4 ;
      RECT 1.000 47.604 4.000 47.652 ;
    END
  END wd_in[55]
  PIN wd_in[56]
    DIRECTION INPUT ;
    USE SIGNAL ;
    PORT
      LAYER M4 ;
      RECT 1.000 47.760 3.000 47.784 ;
    END
    PORT
      LAYER M4 ;
      RECT 1.000 47.748 4.000 47.796 ;
    END
  END wd_in[56]
  PIN wd_in[57]
    DIRECTION INPUT ;
    USE SIGNAL ;
    PORT
      LAYER M4 ;
      RECT 1.000 47.904 3.000 47.928 ;
    END
    PORT
      LAYER M4 ;
      RECT 1.000 47.892 4.000 47.940 ;
    END
  END wd_in[57]
  PIN wd_in[58]
    DIRECTION INPUT ;
    USE SIGNAL ;
    PORT
      LAYER M4 ;
      RECT 1.000 48.048 3.000 48.072 ;
    END
    PORT
      LAYER M4 ;
      RECT 1.000 48.036 4.000 48.084 ;
    END
  END wd_in[58]
  PIN wd_in[59]
    DIRECTION INPUT ;
    USE SIGNAL ;
    PORT
      LAYER M4 ;
      RECT 1.000 48.192 3.000 48.216 ;
    END
    PORT
      LAYER M4 ;
      RECT 1.000 48.180 4.000 48.228 ;
    END
  END wd_in[59]
  PIN wd_in[60]
    DIRECTION INPUT ;
    USE SIGNAL ;
    PORT
      LAYER M4 ;
      RECT 1.000 48.336 3.000 48.360 ;
    END
    PORT
      LAYER M4 ;
      RECT 1.000 48.324 4.000 48.372 ;
    END
  END wd_in[60]
  PIN wd_in[61]
    DIRECTION INPUT ;
    USE SIGNAL ;
    PORT
      LAYER M4 ;
      RECT 1.000 48.480 3.000 48.504 ;
    END
    PORT
      LAYER M4 ;
      RECT 1.000 48.468 4.000 48.516 ;
    END
  END wd_in[61]
  PIN wd_in[62]
    DIRECTION INPUT ;
    USE SIGNAL ;
    PORT
      LAYER M4 ;
      RECT 1.000 48.624 3.000 48.648 ;
    END
    PORT
      LAYER M4 ;
      RECT 1.000 48.612 4.000 48.660 ;
    END
  END wd_in[62]
  PIN wd_in[63]
    DIRECTION INPUT ;
    USE SIGNAL ;
    PORT
      LAYER M4 ;
      RECT 1.000 48.768 3.000 48.792 ;
    END
    PORT
      LAYER M4 ;
      RECT 1.000 48.756 4.000 48.804 ;
    END
  END wd_in[63]
  PIN wd_in[64]
    DIRECTION INPUT ;
    USE SIGNAL ;
    PORT
      LAYER M4 ;
      RECT 1.000 48.912 3.000 48.936 ;
    END
    PORT
      LAYER M4 ;
      RECT 1.000 48.900 4.000 48.948 ;
    END
  END wd_in[64]
  PIN wd_in[65]
    DIRECTION INPUT ;
    USE SIGNAL ;
    PORT
      LAYER M4 ;
      RECT 1.000 49.056 3.000 49.080 ;
    END
    PORT
      LAYER M4 ;
      RECT 1.000 49.044 4.000 49.092 ;
    END
  END wd_in[65]
  PIN wd_in[66]
    DIRECTION INPUT ;
    USE SIGNAL ;
    PORT
      LAYER M4 ;
      RECT 1.000 49.200 3.000 49.224 ;
    END
    PORT
      LAYER M4 ;
      RECT 1.000 49.188 4.000 49.236 ;
    END
  END wd_in[66]
  PIN wd_in[67]
    DIRECTION INPUT ;
    USE SIGNAL ;
    PORT
      LAYER M4 ;
      RECT 1.000 49.344 3.000 49.368 ;
    END
    PORT
      LAYER M4 ;
      RECT 1.000 49.332 4.000 49.380 ;
    END
  END wd_in[67]
  PIN wd_in[68]
    DIRECTION INPUT ;
    USE SIGNAL ;
    PORT
      LAYER M4 ;
      RECT 1.000 49.488 3.000 49.512 ;
    END
    PORT
      LAYER M4 ;
      RECT 1.000 49.476 4.000 49.524 ;
    END
  END wd_in[68]
  PIN wd_in[69]
    DIRECTION INPUT ;
    USE SIGNAL ;
    PORT
      LAYER M4 ;
      RECT 1.000 49.632 3.000 49.656 ;
    END
    PORT
      LAYER M4 ;
      RECT 1.000 49.620 4.000 49.668 ;
    END
  END wd_in[69]
  PIN wd_in[70]
    DIRECTION INPUT ;
    USE SIGNAL ;
    PORT
      LAYER M4 ;
      RECT 1.000 49.776 3.000 49.800 ;
    END
    PORT
      LAYER M4 ;
      RECT 1.000 49.764 4.000 49.812 ;
    END
  END wd_in[70]
  PIN wd_in[71]
    DIRECTION INPUT ;
    USE SIGNAL ;
    PORT
      LAYER M4 ;
      RECT 1.000 49.920 3.000 49.944 ;
    END
    PORT
      LAYER M4 ;
      RECT 1.000 49.908 4.000 49.956 ;
    END
  END wd_in[71]
  PIN wd_in[72]
    DIRECTION INPUT ;
    USE SIGNAL ;
    PORT
      LAYER M4 ;
      RECT 1.000 50.064 3.000 50.088 ;
    END
    PORT
      LAYER M4 ;
      RECT 1.000 50.052 4.000 50.100 ;
    END
  END wd_in[72]
  PIN wd_in[73]
    DIRECTION INPUT ;
    USE SIGNAL ;
    PORT
      LAYER M4 ;
      RECT 1.000 50.208 3.000 50.232 ;
    END
    PORT
      LAYER M4 ;
      RECT 1.000 50.196 4.000 50.244 ;
    END
  END wd_in[73]
  PIN wd_in[74]
    DIRECTION INPUT ;
    USE SIGNAL ;
    PORT
      LAYER M4 ;
      RECT 1.000 50.352 3.000 50.376 ;
    END
    PORT
      LAYER M4 ;
      RECT 1.000 50.340 4.000 50.388 ;
    END
  END wd_in[74]
  PIN wd_in[75]
    DIRECTION INPUT ;
    USE SIGNAL ;
    PORT
      LAYER M4 ;
      RECT 1.000 50.496 3.000 50.520 ;
    END
    PORT
      LAYER M4 ;
      RECT 1.000 50.484 4.000 50.532 ;
    END
  END wd_in[75]
  PIN wd_in[76]
    DIRECTION INPUT ;
    USE SIGNAL ;
    PORT
      LAYER M4 ;
      RECT 1.000 50.640 3.000 50.664 ;
    END
    PORT
      LAYER M4 ;
      RECT 1.000 50.628 4.000 50.676 ;
    END
  END wd_in[76]
  PIN wd_in[77]
    DIRECTION INPUT ;
    USE SIGNAL ;
    PORT
      LAYER M4 ;
      RECT 1.000 50.784 3.000 50.808 ;
    END
    PORT
      LAYER M4 ;
      RECT 1.000 50.772 4.000 50.820 ;
    END
  END wd_in[77]
  PIN wd_in[78]
    DIRECTION INPUT ;
    USE SIGNAL ;
    PORT
      LAYER M4 ;
      RECT 1.000 50.928 3.000 50.952 ;
    END
    PORT
      LAYER M4 ;
      RECT 1.000 50.916 4.000 50.964 ;
    END
  END wd_in[78]
  PIN wd_in[79]
    DIRECTION INPUT ;
    USE SIGNAL ;
    PORT
      LAYER M4 ;
      RECT 1.000 51.072 3.000 51.096 ;
    END
    PORT
      LAYER M4 ;
      RECT 1.000 51.060 4.000 51.108 ;
    END
  END wd_in[79]
  PIN wd_in[80]
    DIRECTION INPUT ;
    USE SIGNAL ;
    PORT
      LAYER M4 ;
      RECT 1.000 51.216 3.000 51.240 ;
    END
    PORT
      LAYER M4 ;
      RECT 1.000 51.204 4.000 51.252 ;
    END
  END wd_in[80]
  PIN wd_in[81]
    DIRECTION INPUT ;
    USE SIGNAL ;
    PORT
      LAYER M4 ;
      RECT 1.000 51.360 3.000 51.384 ;
    END
    PORT
      LAYER M4 ;
      RECT 1.000 51.348 4.000 51.396 ;
    END
  END wd_in[81]
  PIN wd_in[82]
    DIRECTION INPUT ;
    USE SIGNAL ;
    PORT
      LAYER M4 ;
      RECT 1.000 51.504 3.000 51.528 ;
    END
    PORT
      LAYER M4 ;
      RECT 1.000 51.492 4.000 51.540 ;
    END
  END wd_in[82]
  PIN wd_in[83]
    DIRECTION INPUT ;
    USE SIGNAL ;
    PORT
      LAYER M4 ;
      RECT 1.000 51.648 3.000 51.672 ;
    END
    PORT
      LAYER M4 ;
      RECT 1.000 51.636 4.000 51.684 ;
    END
  END wd_in[83]
  PIN wd_in[84]
    DIRECTION INPUT ;
    USE SIGNAL ;
    PORT
      LAYER M4 ;
      RECT 1.000 51.792 3.000 51.816 ;
    END
    PORT
      LAYER M4 ;
      RECT 1.000 51.780 4.000 51.828 ;
    END
  END wd_in[84]
  PIN wd_in[85]
    DIRECTION INPUT ;
    USE SIGNAL ;
    PORT
      LAYER M4 ;
      RECT 1.000 51.936 3.000 51.960 ;
    END
    PORT
      LAYER M4 ;
      RECT 1.000 51.924 4.000 51.972 ;
    END
  END wd_in[85]
  PIN wd_in[86]
    DIRECTION INPUT ;
    USE SIGNAL ;
    PORT
      LAYER M4 ;
      RECT 1.000 52.080 3.000 52.104 ;
    END
    PORT
      LAYER M4 ;
      RECT 1.000 52.068 4.000 52.116 ;
    END
  END wd_in[86]
  PIN wd_in[87]
    DIRECTION INPUT ;
    USE SIGNAL ;
    PORT
      LAYER M4 ;
      RECT 1.000 52.224 3.000 52.248 ;
    END
    PORT
      LAYER M4 ;
      RECT 1.000 52.212 4.000 52.260 ;
    END
  END wd_in[87]
  PIN wd_in[88]
    DIRECTION INPUT ;
    USE SIGNAL ;
    PORT
      LAYER M4 ;
      RECT 1.000 52.368 3.000 52.392 ;
    END
    PORT
      LAYER M4 ;
      RECT 1.000 52.356 4.000 52.404 ;
    END
  END wd_in[88]
  PIN wd_in[89]
    DIRECTION INPUT ;
    USE SIGNAL ;
    PORT
      LAYER M4 ;
      RECT 1.000 52.512 3.000 52.536 ;
    END
    PORT
      LAYER M4 ;
      RECT 1.000 52.500 4.000 52.548 ;
    END
  END wd_in[89]
  PIN wd_in[90]
    DIRECTION INPUT ;
    USE SIGNAL ;
    PORT
      LAYER M4 ;
      RECT 1.000 52.656 3.000 52.680 ;
    END
    PORT
      LAYER M4 ;
      RECT 1.000 52.644 4.000 52.692 ;
    END
  END wd_in[90]
  PIN wd_in[91]
    DIRECTION INPUT ;
    USE SIGNAL ;
    PORT
      LAYER M4 ;
      RECT 1.000 52.800 3.000 52.824 ;
    END
    PORT
      LAYER M4 ;
      RECT 1.000 52.788 4.000 52.836 ;
    END
  END wd_in[91]
  PIN wd_in[92]
    DIRECTION INPUT ;
    USE SIGNAL ;
    PORT
      LAYER M4 ;
      RECT 1.000 52.944 3.000 52.968 ;
    END
    PORT
      LAYER M4 ;
      RECT 1.000 52.932 4.000 52.980 ;
    END
  END wd_in[92]
  PIN wd_in[93]
    DIRECTION INPUT ;
    USE SIGNAL ;
    PORT
      LAYER M4 ;
      RECT 1.000 53.088 3.000 53.112 ;
    END
    PORT
      LAYER M4 ;
      RECT 1.000 53.076 4.000 53.124 ;
    END
  END wd_in[93]
  PIN wd_in[94]
    DIRECTION INPUT ;
    USE SIGNAL ;
    PORT
      LAYER M4 ;
      RECT 1.000 53.232 3.000 53.256 ;
    END
    PORT
      LAYER M4 ;
      RECT 1.000 53.220 4.000 53.268 ;
    END
  END wd_in[94]
  PIN wd_in[95]
    DIRECTION INPUT ;
    USE SIGNAL ;
    PORT
      LAYER M4 ;
      RECT 1.000 53.376 3.000 53.400 ;
    END
    PORT
      LAYER M4 ;
      RECT 1.000 53.364 4.000 53.412 ;
    END
  END wd_in[95]
  PIN wd_in[96]
    DIRECTION INPUT ;
    USE SIGNAL ;
    PORT
      LAYER M4 ;
      RECT 1.000 53.520 3.000 53.544 ;
    END
    PORT
      LAYER M4 ;
      RECT 1.000 53.508 4.000 53.556 ;
    END
  END wd_in[96]
  PIN wd_in[97]
    DIRECTION INPUT ;
    USE SIGNAL ;
    PORT
      LAYER M4 ;
      RECT 1.000 53.664 3.000 53.688 ;
    END
    PORT
      LAYER M4 ;
      RECT 1.000 53.652 4.000 53.700 ;
    END
  END wd_in[97]
  PIN wd_in[98]
    DIRECTION INPUT ;
    USE SIGNAL ;
    PORT
      LAYER M4 ;
      RECT 1.000 53.808 3.000 53.832 ;
    END
    PORT
      LAYER M4 ;
      RECT 1.000 53.796 4.000 53.844 ;
    END
  END wd_in[98]
  PIN wd_in[99]
    DIRECTION INPUT ;
    USE SIGNAL ;
    PORT
      LAYER M4 ;
      RECT 1.000 53.952 3.000 53.976 ;
    END
    PORT
      LAYER M4 ;
      RECT 1.000 53.940 4.000 53.988 ;
    END
  END wd_in[99]
  PIN wd_in[100]
    DIRECTION INPUT ;
    USE SIGNAL ;
    PORT
      LAYER M4 ;
      RECT 1.000 54.096 3.000 54.120 ;
    END
    PORT
      LAYER M4 ;
      RECT 1.000 54.084 4.000 54.132 ;
    END
  END wd_in[100]
  PIN wd_in[101]
    DIRECTION INPUT ;
    USE SIGNAL ;
    PORT
      LAYER M4 ;
      RECT 1.000 54.240 3.000 54.264 ;
    END
    PORT
      LAYER M4 ;
      RECT 1.000 54.228 4.000 54.276 ;
    END
  END wd_in[101]
  PIN wd_in[102]
    DIRECTION INPUT ;
    USE SIGNAL ;
    PORT
      LAYER M4 ;
      RECT 1.000 54.384 3.000 54.408 ;
    END
    PORT
      LAYER M4 ;
      RECT 1.000 54.372 4.000 54.420 ;
    END
  END wd_in[102]
  PIN wd_in[103]
    DIRECTION INPUT ;
    USE SIGNAL ;
    PORT
      LAYER M4 ;
      RECT 1.000 54.528 3.000 54.552 ;
    END
    PORT
      LAYER M4 ;
      RECT 1.000 54.516 4.000 54.564 ;
    END
  END wd_in[103]
  PIN wd_in[104]
    DIRECTION INPUT ;
    USE SIGNAL ;
    PORT
      LAYER M4 ;
      RECT 1.000 54.672 3.000 54.696 ;
    END
    PORT
      LAYER M4 ;
      RECT 1.000 54.660 4.000 54.708 ;
    END
  END wd_in[104]
  PIN wd_in[105]
    DIRECTION INPUT ;
    USE SIGNAL ;
    PORT
      LAYER M4 ;
      RECT 1.000 54.816 3.000 54.840 ;
    END
    PORT
      LAYER M4 ;
      RECT 1.000 54.804 4.000 54.852 ;
    END
  END wd_in[105]
  PIN wd_in[106]
    DIRECTION INPUT ;
    USE SIGNAL ;
    PORT
      LAYER M4 ;
      RECT 1.000 54.960 3.000 54.984 ;
    END
    PORT
      LAYER M4 ;
      RECT 1.000 54.948 4.000 54.996 ;
    END
  END wd_in[106]
  PIN wd_in[107]
    DIRECTION INPUT ;
    USE SIGNAL ;
    PORT
      LAYER M4 ;
      RECT 1.000 55.104 3.000 55.128 ;
    END
    PORT
      LAYER M4 ;
      RECT 1.000 55.092 4.000 55.140 ;
    END
  END wd_in[107]
  PIN wd_in[108]
    DIRECTION INPUT ;
    USE SIGNAL ;
    PORT
      LAYER M4 ;
      RECT 1.000 55.248 3.000 55.272 ;
    END
    PORT
      LAYER M4 ;
      RECT 1.000 55.236 4.000 55.284 ;
    END
  END wd_in[108]
  PIN wd_in[109]
    DIRECTION INPUT ;
    USE SIGNAL ;
    PORT
      LAYER M4 ;
      RECT 1.000 55.392 3.000 55.416 ;
    END
    PORT
      LAYER M4 ;
      RECT 1.000 55.380 4.000 55.428 ;
    END
  END wd_in[109]
  PIN wd_in[110]
    DIRECTION INPUT ;
    USE SIGNAL ;
    PORT
      LAYER M4 ;
      RECT 1.000 55.536 3.000 55.560 ;
    END
    PORT
      LAYER M4 ;
      RECT 1.000 55.524 4.000 55.572 ;
    END
  END wd_in[110]
  PIN wd_in[111]
    DIRECTION INPUT ;
    USE SIGNAL ;
    PORT
      LAYER M4 ;
      RECT 1.000 55.680 3.000 55.704 ;
    END
    PORT
      LAYER M4 ;
      RECT 1.000 55.668 4.000 55.716 ;
    END
  END wd_in[111]
  PIN wd_in[112]
    DIRECTION INPUT ;
    USE SIGNAL ;
    PORT
      LAYER M4 ;
      RECT 1.000 55.824 3.000 55.848 ;
    END
    PORT
      LAYER M4 ;
      RECT 1.000 55.812 4.000 55.860 ;
    END
  END wd_in[112]
  PIN wd_in[113]
    DIRECTION INPUT ;
    USE SIGNAL ;
    PORT
      LAYER M4 ;
      RECT 1.000 55.968 3.000 55.992 ;
    END
    PORT
      LAYER M4 ;
      RECT 1.000 55.956 4.000 56.004 ;
    END
  END wd_in[113]
  PIN wd_in[114]
    DIRECTION INPUT ;
    USE SIGNAL ;
    PORT
      LAYER M4 ;
      RECT 1.000 56.112 3.000 56.136 ;
    END
    PORT
      LAYER M4 ;
      RECT 1.000 56.100 4.000 56.148 ;
    END
  END wd_in[114]
  PIN wd_in[115]
    DIRECTION INPUT ;
    USE SIGNAL ;
    PORT
      LAYER M4 ;
      RECT 1.000 56.256 3.000 56.280 ;
    END
    PORT
      LAYER M4 ;
      RECT 1.000 56.244 4.000 56.292 ;
    END
  END wd_in[115]
  PIN wd_in[116]
    DIRECTION INPUT ;
    USE SIGNAL ;
    PORT
      LAYER M4 ;
      RECT 1.000 56.400 3.000 56.424 ;
    END
    PORT
      LAYER M4 ;
      RECT 1.000 56.388 4.000 56.436 ;
    END
  END wd_in[116]
  PIN wd_in[117]
    DIRECTION INPUT ;
    USE SIGNAL ;
    PORT
      LAYER M4 ;
      RECT 1.000 56.544 3.000 56.568 ;
    END
    PORT
      LAYER M4 ;
      RECT 1.000 56.532 4.000 56.580 ;
    END
  END wd_in[117]
  PIN wd_in[118]
    DIRECTION INPUT ;
    USE SIGNAL ;
    PORT
      LAYER M4 ;
      RECT 1.000 56.688 3.000 56.712 ;
    END
    PORT
      LAYER M4 ;
      RECT 1.000 56.676 4.000 56.724 ;
    END
  END wd_in[118]
  PIN wd_in[119]
    DIRECTION INPUT ;
    USE SIGNAL ;
    PORT
      LAYER M4 ;
      RECT 1.000 56.832 3.000 56.856 ;
    END
    PORT
      LAYER M4 ;
      RECT 1.000 56.820 4.000 56.868 ;
    END
  END wd_in[119]
  PIN wd_in[120]
    DIRECTION INPUT ;
    USE SIGNAL ;
    PORT
      LAYER M4 ;
      RECT 1.000 56.976 3.000 57.000 ;
    END
    PORT
      LAYER M4 ;
      RECT 1.000 56.964 4.000 57.012 ;
    END
  END wd_in[120]
  PIN wd_in[121]
    DIRECTION INPUT ;
    USE SIGNAL ;
    PORT
      LAYER M4 ;
      RECT 1.000 57.120 3.000 57.144 ;
    END
    PORT
      LAYER M4 ;
      RECT 1.000 57.108 4.000 57.156 ;
    END
  END wd_in[121]
  PIN wd_in[122]
    DIRECTION INPUT ;
    USE SIGNAL ;
    PORT
      LAYER M4 ;
      RECT 1.000 57.264 3.000 57.288 ;
    END
    PORT
      LAYER M4 ;
      RECT 1.000 57.252 4.000 57.300 ;
    END
  END wd_in[122]
  PIN wd_in[123]
    DIRECTION INPUT ;
    USE SIGNAL ;
    PORT
      LAYER M4 ;
      RECT 1.000 57.408 3.000 57.432 ;
    END
    PORT
      LAYER M4 ;
      RECT 1.000 57.396 4.000 57.444 ;
    END
  END wd_in[123]
  PIN wd_in[124]
    DIRECTION INPUT ;
    USE SIGNAL ;
    PORT
      LAYER M4 ;
      RECT 1.000 57.552 3.000 57.576 ;
    END
    PORT
      LAYER M4 ;
      RECT 1.000 57.540 4.000 57.588 ;
    END
  END wd_in[124]
  PIN wd_in[125]
    DIRECTION INPUT ;
    USE SIGNAL ;
    PORT
      LAYER M4 ;
      RECT 1.000 57.696 3.000 57.720 ;
    END
    PORT
      LAYER M4 ;
      RECT 1.000 57.684 4.000 57.732 ;
    END
  END wd_in[125]
  PIN wd_in[126]
    DIRECTION INPUT ;
    USE SIGNAL ;
    PORT
      LAYER M4 ;
      RECT 1.000 57.840 3.000 57.864 ;
    END
    PORT
      LAYER M4 ;
      RECT 1.000 57.828 4.000 57.876 ;
    END
  END wd_in[126]
  PIN wd_in[127]
    DIRECTION INPUT ;
    USE SIGNAL ;
    PORT
      LAYER M4 ;
      RECT 1.000 57.984 3.000 58.008 ;
    END
    PORT
      LAYER M4 ;
      RECT 1.000 57.972 4.000 58.020 ;
    END
  END wd_in[127]
  PIN wd_in[128]
    DIRECTION INPUT ;
    USE SIGNAL ;
    PORT
      LAYER M4 ;
      RECT 1.000 58.128 3.000 58.152 ;
    END
    PORT
      LAYER M4 ;
      RECT 1.000 58.116 4.000 58.164 ;
    END
  END wd_in[128]
  PIN wd_in[129]
    DIRECTION INPUT ;
    USE SIGNAL ;
    PORT
      LAYER M4 ;
      RECT 1.000 58.272 3.000 58.296 ;
    END
    PORT
      LAYER M4 ;
      RECT 1.000 58.260 4.000 58.308 ;
    END
  END wd_in[129]
  PIN wd_in[130]
    DIRECTION INPUT ;
    USE SIGNAL ;
    PORT
      LAYER M4 ;
      RECT 1.000 58.416 3.000 58.440 ;
    END
    PORT
      LAYER M4 ;
      RECT 1.000 58.404 4.000 58.452 ;
    END
  END wd_in[130]
  PIN wd_in[131]
    DIRECTION INPUT ;
    USE SIGNAL ;
    PORT
      LAYER M4 ;
      RECT 1.000 58.560 3.000 58.584 ;
    END
    PORT
      LAYER M4 ;
      RECT 1.000 58.548 4.000 58.596 ;
    END
  END wd_in[131]
  PIN wd_in[132]
    DIRECTION INPUT ;
    USE SIGNAL ;
    PORT
      LAYER M4 ;
      RECT 1.000 58.704 3.000 58.728 ;
    END
    PORT
      LAYER M4 ;
      RECT 1.000 58.692 4.000 58.740 ;
    END
  END wd_in[132]
  PIN wd_in[133]
    DIRECTION INPUT ;
    USE SIGNAL ;
    PORT
      LAYER M4 ;
      RECT 1.000 58.848 3.000 58.872 ;
    END
    PORT
      LAYER M4 ;
      RECT 1.000 58.836 4.000 58.884 ;
    END
  END wd_in[133]
  PIN wd_in[134]
    DIRECTION INPUT ;
    USE SIGNAL ;
    PORT
      LAYER M4 ;
      RECT 1.000 58.992 3.000 59.016 ;
    END
    PORT
      LAYER M4 ;
      RECT 1.000 58.980 4.000 59.028 ;
    END
  END wd_in[134]
  PIN wd_in[135]
    DIRECTION INPUT ;
    USE SIGNAL ;
    PORT
      LAYER M4 ;
      RECT 1.000 59.136 3.000 59.160 ;
    END
    PORT
      LAYER M4 ;
      RECT 1.000 59.124 4.000 59.172 ;
    END
  END wd_in[135]
  PIN wd_in[136]
    DIRECTION INPUT ;
    USE SIGNAL ;
    PORT
      LAYER M4 ;
      RECT 1.000 59.280 3.000 59.304 ;
    END
    PORT
      LAYER M4 ;
      RECT 1.000 59.268 4.000 59.316 ;
    END
  END wd_in[136]
  PIN wd_in[137]
    DIRECTION INPUT ;
    USE SIGNAL ;
    PORT
      LAYER M4 ;
      RECT 1.000 59.424 3.000 59.448 ;
    END
    PORT
      LAYER M4 ;
      RECT 1.000 59.412 4.000 59.460 ;
    END
  END wd_in[137]
  PIN wd_in[138]
    DIRECTION INPUT ;
    USE SIGNAL ;
    PORT
      LAYER M4 ;
      RECT 1.000 59.568 3.000 59.592 ;
    END
    PORT
      LAYER M4 ;
      RECT 1.000 59.556 4.000 59.604 ;
    END
  END wd_in[138]
  PIN wd_in[139]
    DIRECTION INPUT ;
    USE SIGNAL ;
    PORT
      LAYER M4 ;
      RECT 1.000 59.712 3.000 59.736 ;
    END
    PORT
      LAYER M4 ;
      RECT 1.000 59.700 4.000 59.748 ;
    END
  END wd_in[139]
  PIN wd_in[140]
    DIRECTION INPUT ;
    USE SIGNAL ;
    PORT
      LAYER M4 ;
      RECT 1.000 59.856 3.000 59.880 ;
    END
    PORT
      LAYER M4 ;
      RECT 1.000 59.844 4.000 59.892 ;
    END
  END wd_in[140]
  PIN wd_in[141]
    DIRECTION INPUT ;
    USE SIGNAL ;
    PORT
      LAYER M4 ;
      RECT 1.000 60.000 3.000 60.024 ;
    END
    PORT
      LAYER M4 ;
      RECT 1.000 59.988 4.000 60.036 ;
    END
  END wd_in[141]
  PIN wd_in[142]
    DIRECTION INPUT ;
    USE SIGNAL ;
    PORT
      LAYER M4 ;
      RECT 1.000 60.144 3.000 60.168 ;
    END
    PORT
      LAYER M4 ;
      RECT 1.000 60.132 4.000 60.180 ;
    END
  END wd_in[142]
  PIN wd_in[143]
    DIRECTION INPUT ;
    USE SIGNAL ;
    PORT
      LAYER M4 ;
      RECT 1.000 60.288 3.000 60.312 ;
    END
    PORT
      LAYER M4 ;
      RECT 1.000 60.276 4.000 60.324 ;
    END
  END wd_in[143]
  PIN wd_in[144]
    DIRECTION INPUT ;
    USE SIGNAL ;
    PORT
      LAYER M4 ;
      RECT 1.000 60.432 3.000 60.456 ;
    END
    PORT
      LAYER M4 ;
      RECT 1.000 60.420 4.000 60.468 ;
    END
  END wd_in[144]
  PIN wd_in[145]
    DIRECTION INPUT ;
    USE SIGNAL ;
    PORT
      LAYER M4 ;
      RECT 1.000 60.576 3.000 60.600 ;
    END
    PORT
      LAYER M4 ;
      RECT 1.000 60.564 4.000 60.612 ;
    END
  END wd_in[145]
  PIN wd_in[146]
    DIRECTION INPUT ;
    USE SIGNAL ;
    PORT
      LAYER M4 ;
      RECT 1.000 60.720 3.000 60.744 ;
    END
    PORT
      LAYER M4 ;
      RECT 1.000 60.708 4.000 60.756 ;
    END
  END wd_in[146]
  PIN wd_in[147]
    DIRECTION INPUT ;
    USE SIGNAL ;
    PORT
      LAYER M4 ;
      RECT 1.000 60.864 3.000 60.888 ;
    END
    PORT
      LAYER M4 ;
      RECT 1.000 60.852 4.000 60.900 ;
    END
  END wd_in[147]
  PIN wd_in[148]
    DIRECTION INPUT ;
    USE SIGNAL ;
    PORT
      LAYER M4 ;
      RECT 1.000 61.008 3.000 61.032 ;
    END
    PORT
      LAYER M4 ;
      RECT 1.000 60.996 4.000 61.044 ;
    END
  END wd_in[148]
  PIN wd_in[149]
    DIRECTION INPUT ;
    USE SIGNAL ;
    PORT
      LAYER M4 ;
      RECT 1.000 61.152 3.000 61.176 ;
    END
    PORT
      LAYER M4 ;
      RECT 1.000 61.140 4.000 61.188 ;
    END
  END wd_in[149]
  PIN wd_in[150]
    DIRECTION INPUT ;
    USE SIGNAL ;
    PORT
      LAYER M4 ;
      RECT 1.000 61.296 3.000 61.320 ;
    END
    PORT
      LAYER M4 ;
      RECT 1.000 61.284 4.000 61.332 ;
    END
  END wd_in[150]
  PIN wd_in[151]
    DIRECTION INPUT ;
    USE SIGNAL ;
    PORT
      LAYER M4 ;
      RECT 1.000 61.440 3.000 61.464 ;
    END
    PORT
      LAYER M4 ;
      RECT 1.000 61.428 4.000 61.476 ;
    END
  END wd_in[151]
  PIN wd_in[152]
    DIRECTION INPUT ;
    USE SIGNAL ;
    PORT
      LAYER M4 ;
      RECT 1.000 61.584 3.000 61.608 ;
    END
    PORT
      LAYER M4 ;
      RECT 1.000 61.572 4.000 61.620 ;
    END
  END wd_in[152]
  PIN wd_in[153]
    DIRECTION INPUT ;
    USE SIGNAL ;
    PORT
      LAYER M4 ;
      RECT 1.000 61.728 3.000 61.752 ;
    END
    PORT
      LAYER M4 ;
      RECT 1.000 61.716 4.000 61.764 ;
    END
  END wd_in[153]
  PIN wd_in[154]
    DIRECTION INPUT ;
    USE SIGNAL ;
    PORT
      LAYER M4 ;
      RECT 1.000 61.872 3.000 61.896 ;
    END
    PORT
      LAYER M4 ;
      RECT 1.000 61.860 4.000 61.908 ;
    END
  END wd_in[154]
  PIN wd_in[155]
    DIRECTION INPUT ;
    USE SIGNAL ;
    PORT
      LAYER M4 ;
      RECT 1.000 62.016 3.000 62.040 ;
    END
    PORT
      LAYER M4 ;
      RECT 1.000 62.004 4.000 62.052 ;
    END
  END wd_in[155]
  PIN wd_in[156]
    DIRECTION INPUT ;
    USE SIGNAL ;
    PORT
      LAYER M4 ;
      RECT 1.000 62.160 3.000 62.184 ;
    END
    PORT
      LAYER M4 ;
      RECT 1.000 62.148 4.000 62.196 ;
    END
  END wd_in[156]
  PIN wd_in[157]
    DIRECTION INPUT ;
    USE SIGNAL ;
    PORT
      LAYER M4 ;
      RECT 1.000 62.304 3.000 62.328 ;
    END
    PORT
      LAYER M4 ;
      RECT 1.000 62.292 4.000 62.340 ;
    END
  END wd_in[157]
  PIN wd_in[158]
    DIRECTION INPUT ;
    USE SIGNAL ;
    PORT
      LAYER M4 ;
      RECT 1.000 62.448 3.000 62.472 ;
    END
    PORT
      LAYER M4 ;
      RECT 1.000 62.436 4.000 62.484 ;
    END
  END wd_in[158]
  PIN wd_in[159]
    DIRECTION INPUT ;
    USE SIGNAL ;
    PORT
      LAYER M4 ;
      RECT 1.000 62.592 3.000 62.616 ;
    END
    PORT
      LAYER M4 ;
      RECT 1.000 62.580 4.000 62.628 ;
    END
  END wd_in[159]
  PIN wd_in[160]
    DIRECTION INPUT ;
    USE SIGNAL ;
    PORT
      LAYER M4 ;
      RECT 1.000 62.736 3.000 62.760 ;
    END
    PORT
      LAYER M4 ;
      RECT 1.000 62.724 4.000 62.772 ;
    END
  END wd_in[160]
  PIN wd_in[161]
    DIRECTION INPUT ;
    USE SIGNAL ;
    PORT
      LAYER M4 ;
      RECT 1.000 62.880 3.000 62.904 ;
    END
    PORT
      LAYER M4 ;
      RECT 1.000 62.868 4.000 62.916 ;
    END
  END wd_in[161]
  PIN wd_in[162]
    DIRECTION INPUT ;
    USE SIGNAL ;
    PORT
      LAYER M4 ;
      RECT 1.000 63.024 3.000 63.048 ;
    END
    PORT
      LAYER M4 ;
      RECT 1.000 63.012 4.000 63.060 ;
    END
  END wd_in[162]
  PIN wd_in[163]
    DIRECTION INPUT ;
    USE SIGNAL ;
    PORT
      LAYER M4 ;
      RECT 1.000 63.168 3.000 63.192 ;
    END
    PORT
      LAYER M4 ;
      RECT 1.000 63.156 4.000 63.204 ;
    END
  END wd_in[163]
  PIN wd_in[164]
    DIRECTION INPUT ;
    USE SIGNAL ;
    PORT
      LAYER M4 ;
      RECT 1.000 63.312 3.000 63.336 ;
    END
    PORT
      LAYER M4 ;
      RECT 1.000 63.300 4.000 63.348 ;
    END
  END wd_in[164]
  PIN wd_in[165]
    DIRECTION INPUT ;
    USE SIGNAL ;
    PORT
      LAYER M4 ;
      RECT 1.000 63.456 3.000 63.480 ;
    END
    PORT
      LAYER M4 ;
      RECT 1.000 63.444 4.000 63.492 ;
    END
  END wd_in[165]
  PIN wd_in[166]
    DIRECTION INPUT ;
    USE SIGNAL ;
    PORT
      LAYER M4 ;
      RECT 1.000 63.600 3.000 63.624 ;
    END
    PORT
      LAYER M4 ;
      RECT 1.000 63.588 4.000 63.636 ;
    END
  END wd_in[166]
  PIN wd_in[167]
    DIRECTION INPUT ;
    USE SIGNAL ;
    PORT
      LAYER M4 ;
      RECT 1.000 63.744 3.000 63.768 ;
    END
    PORT
      LAYER M4 ;
      RECT 1.000 63.732 4.000 63.780 ;
    END
  END wd_in[167]
  PIN wd_in[168]
    DIRECTION INPUT ;
    USE SIGNAL ;
    PORT
      LAYER M4 ;
      RECT 1.000 63.888 3.000 63.912 ;
    END
    PORT
      LAYER M4 ;
      RECT 1.000 63.876 4.000 63.924 ;
    END
  END wd_in[168]
  PIN wd_in[169]
    DIRECTION INPUT ;
    USE SIGNAL ;
    PORT
      LAYER M4 ;
      RECT 1.000 64.032 3.000 64.056 ;
    END
    PORT
      LAYER M4 ;
      RECT 1.000 64.020 4.000 64.068 ;
    END
  END wd_in[169]
  PIN wd_in[170]
    DIRECTION INPUT ;
    USE SIGNAL ;
    PORT
      LAYER M4 ;
      RECT 1.000 64.176 3.000 64.200 ;
    END
    PORT
      LAYER M4 ;
      RECT 1.000 64.164 4.000 64.212 ;
    END
  END wd_in[170]
  PIN wd_in[171]
    DIRECTION INPUT ;
    USE SIGNAL ;
    PORT
      LAYER M4 ;
      RECT 1.000 64.320 3.000 64.344 ;
    END
    PORT
      LAYER M4 ;
      RECT 1.000 64.308 4.000 64.356 ;
    END
  END wd_in[171]
  PIN wd_in[172]
    DIRECTION INPUT ;
    USE SIGNAL ;
    PORT
      LAYER M4 ;
      RECT 1.000 64.464 3.000 64.488 ;
    END
    PORT
      LAYER M4 ;
      RECT 1.000 64.452 4.000 64.500 ;
    END
  END wd_in[172]
  PIN wd_in[173]
    DIRECTION INPUT ;
    USE SIGNAL ;
    PORT
      LAYER M4 ;
      RECT 1.000 64.608 3.000 64.632 ;
    END
    PORT
      LAYER M4 ;
      RECT 1.000 64.596 4.000 64.644 ;
    END
  END wd_in[173]
  PIN wd_in[174]
    DIRECTION INPUT ;
    USE SIGNAL ;
    PORT
      LAYER M4 ;
      RECT 1.000 64.752 3.000 64.776 ;
    END
    PORT
      LAYER M4 ;
      RECT 1.000 64.740 4.000 64.788 ;
    END
  END wd_in[174]
  PIN wd_in[175]
    DIRECTION INPUT ;
    USE SIGNAL ;
    PORT
      LAYER M4 ;
      RECT 1.000 64.896 3.000 64.920 ;
    END
    PORT
      LAYER M4 ;
      RECT 1.000 64.884 4.000 64.932 ;
    END
  END wd_in[175]
  PIN wd_in[176]
    DIRECTION INPUT ;
    USE SIGNAL ;
    PORT
      LAYER M4 ;
      RECT 1.000 65.040 3.000 65.064 ;
    END
    PORT
      LAYER M4 ;
      RECT 1.000 65.028 4.000 65.076 ;
    END
  END wd_in[176]
  PIN wd_in[177]
    DIRECTION INPUT ;
    USE SIGNAL ;
    PORT
      LAYER M4 ;
      RECT 1.000 65.184 3.000 65.208 ;
    END
    PORT
      LAYER M4 ;
      RECT 1.000 65.172 4.000 65.220 ;
    END
  END wd_in[177]
  PIN wd_in[178]
    DIRECTION INPUT ;
    USE SIGNAL ;
    PORT
      LAYER M4 ;
      RECT 1.000 65.328 3.000 65.352 ;
    END
    PORT
      LAYER M4 ;
      RECT 1.000 65.316 4.000 65.364 ;
    END
  END wd_in[178]
  PIN wd_in[179]
    DIRECTION INPUT ;
    USE SIGNAL ;
    PORT
      LAYER M4 ;
      RECT 1.000 65.472 3.000 65.496 ;
    END
    PORT
      LAYER M4 ;
      RECT 1.000 65.460 4.000 65.508 ;
    END
  END wd_in[179]
  PIN wd_in[180]
    DIRECTION INPUT ;
    USE SIGNAL ;
    PORT
      LAYER M4 ;
      RECT 1.000 65.616 3.000 65.640 ;
    END
    PORT
      LAYER M4 ;
      RECT 1.000 65.604 4.000 65.652 ;
    END
  END wd_in[180]
  PIN wd_in[181]
    DIRECTION INPUT ;
    USE SIGNAL ;
    PORT
      LAYER M4 ;
      RECT 1.000 65.760 3.000 65.784 ;
    END
    PORT
      LAYER M4 ;
      RECT 1.000 65.748 4.000 65.796 ;
    END
  END wd_in[181]
  PIN wd_in[182]
    DIRECTION INPUT ;
    USE SIGNAL ;
    PORT
      LAYER M4 ;
      RECT 1.000 65.904 3.000 65.928 ;
    END
    PORT
      LAYER M4 ;
      RECT 1.000 65.892 4.000 65.940 ;
    END
  END wd_in[182]
  PIN wd_in[183]
    DIRECTION INPUT ;
    USE SIGNAL ;
    PORT
      LAYER M4 ;
      RECT 1.000 66.048 3.000 66.072 ;
    END
    PORT
      LAYER M4 ;
      RECT 1.000 66.036 4.000 66.084 ;
    END
  END wd_in[183]
  PIN wd_in[184]
    DIRECTION INPUT ;
    USE SIGNAL ;
    PORT
      LAYER M4 ;
      RECT 1.000 66.192 3.000 66.216 ;
    END
    PORT
      LAYER M4 ;
      RECT 1.000 66.180 4.000 66.228 ;
    END
  END wd_in[184]
  PIN wd_in[185]
    DIRECTION INPUT ;
    USE SIGNAL ;
    PORT
      LAYER M4 ;
      RECT 1.000 66.336 3.000 66.360 ;
    END
    PORT
      LAYER M4 ;
      RECT 1.000 66.324 4.000 66.372 ;
    END
  END wd_in[185]
  PIN wd_in[186]
    DIRECTION INPUT ;
    USE SIGNAL ;
    PORT
      LAYER M4 ;
      RECT 1.000 66.480 3.000 66.504 ;
    END
    PORT
      LAYER M4 ;
      RECT 1.000 66.468 4.000 66.516 ;
    END
  END wd_in[186]
  PIN wd_in[187]
    DIRECTION INPUT ;
    USE SIGNAL ;
    PORT
      LAYER M4 ;
      RECT 1.000 66.624 3.000 66.648 ;
    END
    PORT
      LAYER M4 ;
      RECT 1.000 66.612 4.000 66.660 ;
    END
  END wd_in[187]
  PIN wd_in[188]
    DIRECTION INPUT ;
    USE SIGNAL ;
    PORT
      LAYER M4 ;
      RECT 1.000 66.768 3.000 66.792 ;
    END
    PORT
      LAYER M4 ;
      RECT 1.000 66.756 4.000 66.804 ;
    END
  END wd_in[188]
  PIN wd_in[189]
    DIRECTION INPUT ;
    USE SIGNAL ;
    PORT
      LAYER M4 ;
      RECT 1.000 66.912 3.000 66.936 ;
    END
    PORT
      LAYER M4 ;
      RECT 1.000 66.900 4.000 66.948 ;
    END
  END wd_in[189]
  PIN wd_in[190]
    DIRECTION INPUT ;
    USE SIGNAL ;
    PORT
      LAYER M4 ;
      RECT 1.000 67.056 3.000 67.080 ;
    END
    PORT
      LAYER M4 ;
      RECT 1.000 67.044 4.000 67.092 ;
    END
  END wd_in[190]
  PIN wd_in[191]
    DIRECTION INPUT ;
    USE SIGNAL ;
    PORT
      LAYER M4 ;
      RECT 1.000 67.200 3.000 67.224 ;
    END
    PORT
      LAYER M4 ;
      RECT 1.000 67.188 4.000 67.236 ;
    END
  END wd_in[191]
  PIN wd_in[192]
    DIRECTION INPUT ;
    USE SIGNAL ;
    PORT
      LAYER M4 ;
      RECT 1.000 67.344 3.000 67.368 ;
    END
    PORT
      LAYER M4 ;
      RECT 1.000 67.332 4.000 67.380 ;
    END
  END wd_in[192]
  PIN wd_in[193]
    DIRECTION INPUT ;
    USE SIGNAL ;
    PORT
      LAYER M4 ;
      RECT 1.000 67.488 3.000 67.512 ;
    END
    PORT
      LAYER M4 ;
      RECT 1.000 67.476 4.000 67.524 ;
    END
  END wd_in[193]
  PIN wd_in[194]
    DIRECTION INPUT ;
    USE SIGNAL ;
    PORT
      LAYER M4 ;
      RECT 1.000 67.632 3.000 67.656 ;
    END
    PORT
      LAYER M4 ;
      RECT 1.000 67.620 4.000 67.668 ;
    END
  END wd_in[194]
  PIN wd_in[195]
    DIRECTION INPUT ;
    USE SIGNAL ;
    PORT
      LAYER M4 ;
      RECT 1.000 67.776 3.000 67.800 ;
    END
    PORT
      LAYER M4 ;
      RECT 1.000 67.764 4.000 67.812 ;
    END
  END wd_in[195]
  PIN wd_in[196]
    DIRECTION INPUT ;
    USE SIGNAL ;
    PORT
      LAYER M4 ;
      RECT 1.000 67.920 3.000 67.944 ;
    END
    PORT
      LAYER M4 ;
      RECT 1.000 67.908 4.000 67.956 ;
    END
  END wd_in[196]
  PIN wd_in[197]
    DIRECTION INPUT ;
    USE SIGNAL ;
    PORT
      LAYER M4 ;
      RECT 1.000 68.064 3.000 68.088 ;
    END
    PORT
      LAYER M4 ;
      RECT 1.000 68.052 4.000 68.100 ;
    END
  END wd_in[197]
  PIN wd_in[198]
    DIRECTION INPUT ;
    USE SIGNAL ;
    PORT
      LAYER M4 ;
      RECT 1.000 68.208 3.000 68.232 ;
    END
    PORT
      LAYER M4 ;
      RECT 1.000 68.196 4.000 68.244 ;
    END
  END wd_in[198]
  PIN wd_in[199]
    DIRECTION INPUT ;
    USE SIGNAL ;
    PORT
      LAYER M4 ;
      RECT 1.000 68.352 3.000 68.376 ;
    END
    PORT
      LAYER M4 ;
      RECT 1.000 68.340 4.000 68.388 ;
    END
  END wd_in[199]
  PIN wd_in[200]
    DIRECTION INPUT ;
    USE SIGNAL ;
    PORT
      LAYER M4 ;
      RECT 1.000 68.496 3.000 68.520 ;
    END
    PORT
      LAYER M4 ;
      RECT 1.000 68.484 4.000 68.532 ;
    END
  END wd_in[200]
  PIN wd_in[201]
    DIRECTION INPUT ;
    USE SIGNAL ;
    PORT
      LAYER M4 ;
      RECT 1.000 68.640 3.000 68.664 ;
    END
    PORT
      LAYER M4 ;
      RECT 1.000 68.628 4.000 68.676 ;
    END
  END wd_in[201]
  PIN wd_in[202]
    DIRECTION INPUT ;
    USE SIGNAL ;
    PORT
      LAYER M4 ;
      RECT 1.000 68.784 3.000 68.808 ;
    END
    PORT
      LAYER M4 ;
      RECT 1.000 68.772 4.000 68.820 ;
    END
  END wd_in[202]
  PIN wd_in[203]
    DIRECTION INPUT ;
    USE SIGNAL ;
    PORT
      LAYER M4 ;
      RECT 1.000 68.928 3.000 68.952 ;
    END
    PORT
      LAYER M4 ;
      RECT 1.000 68.916 4.000 68.964 ;
    END
  END wd_in[203]
  PIN wd_in[204]
    DIRECTION INPUT ;
    USE SIGNAL ;
    PORT
      LAYER M4 ;
      RECT 1.000 69.072 3.000 69.096 ;
    END
    PORT
      LAYER M4 ;
      RECT 1.000 69.060 4.000 69.108 ;
    END
  END wd_in[204]
  PIN wd_in[205]
    DIRECTION INPUT ;
    USE SIGNAL ;
    PORT
      LAYER M4 ;
      RECT 1.000 69.216 3.000 69.240 ;
    END
    PORT
      LAYER M4 ;
      RECT 1.000 69.204 4.000 69.252 ;
    END
  END wd_in[205]
  PIN wd_in[206]
    DIRECTION INPUT ;
    USE SIGNAL ;
    PORT
      LAYER M4 ;
      RECT 1.000 69.360 3.000 69.384 ;
    END
    PORT
      LAYER M4 ;
      RECT 1.000 69.348 4.000 69.396 ;
    END
  END wd_in[206]
  PIN wd_in[207]
    DIRECTION INPUT ;
    USE SIGNAL ;
    PORT
      LAYER M4 ;
      RECT 1.000 69.504 3.000 69.528 ;
    END
    PORT
      LAYER M4 ;
      RECT 1.000 69.492 4.000 69.540 ;
    END
  END wd_in[207]
  PIN wd_in[208]
    DIRECTION INPUT ;
    USE SIGNAL ;
    PORT
      LAYER M4 ;
      RECT 1.000 69.648 3.000 69.672 ;
    END
    PORT
      LAYER M4 ;
      RECT 1.000 69.636 4.000 69.684 ;
    END
  END wd_in[208]
  PIN wd_in[209]
    DIRECTION INPUT ;
    USE SIGNAL ;
    PORT
      LAYER M4 ;
      RECT 1.000 69.792 3.000 69.816 ;
    END
    PORT
      LAYER M4 ;
      RECT 1.000 69.780 4.000 69.828 ;
    END
  END wd_in[209]
  PIN wd_in[210]
    DIRECTION INPUT ;
    USE SIGNAL ;
    PORT
      LAYER M4 ;
      RECT 1.000 69.936 3.000 69.960 ;
    END
    PORT
      LAYER M4 ;
      RECT 1.000 69.924 4.000 69.972 ;
    END
  END wd_in[210]
  PIN wd_in[211]
    DIRECTION INPUT ;
    USE SIGNAL ;
    PORT
      LAYER M4 ;
      RECT 1.000 70.080 3.000 70.104 ;
    END
    PORT
      LAYER M4 ;
      RECT 1.000 70.068 4.000 70.116 ;
    END
  END wd_in[211]
  PIN wd_in[212]
    DIRECTION INPUT ;
    USE SIGNAL ;
    PORT
      LAYER M4 ;
      RECT 1.000 70.224 3.000 70.248 ;
    END
    PORT
      LAYER M4 ;
      RECT 1.000 70.212 4.000 70.260 ;
    END
  END wd_in[212]
  PIN wd_in[213]
    DIRECTION INPUT ;
    USE SIGNAL ;
    PORT
      LAYER M4 ;
      RECT 1.000 70.368 3.000 70.392 ;
    END
    PORT
      LAYER M4 ;
      RECT 1.000 70.356 4.000 70.404 ;
    END
  END wd_in[213]
  PIN wd_in[214]
    DIRECTION INPUT ;
    USE SIGNAL ;
    PORT
      LAYER M4 ;
      RECT 1.000 70.512 3.000 70.536 ;
    END
    PORT
      LAYER M4 ;
      RECT 1.000 70.500 4.000 70.548 ;
    END
  END wd_in[214]
  PIN wd_in[215]
    DIRECTION INPUT ;
    USE SIGNAL ;
    PORT
      LAYER M4 ;
      RECT 1.000 70.656 3.000 70.680 ;
    END
    PORT
      LAYER M4 ;
      RECT 1.000 70.644 4.000 70.692 ;
    END
  END wd_in[215]
  PIN wd_in[216]
    DIRECTION INPUT ;
    USE SIGNAL ;
    PORT
      LAYER M4 ;
      RECT 1.000 70.800 3.000 70.824 ;
    END
    PORT
      LAYER M4 ;
      RECT 1.000 70.788 4.000 70.836 ;
    END
  END wd_in[216]
  PIN wd_in[217]
    DIRECTION INPUT ;
    USE SIGNAL ;
    PORT
      LAYER M4 ;
      RECT 1.000 70.944 3.000 70.968 ;
    END
    PORT
      LAYER M4 ;
      RECT 1.000 70.932 4.000 70.980 ;
    END
  END wd_in[217]
  PIN wd_in[218]
    DIRECTION INPUT ;
    USE SIGNAL ;
    PORT
      LAYER M4 ;
      RECT 1.000 71.088 3.000 71.112 ;
    END
    PORT
      LAYER M4 ;
      RECT 1.000 71.076 4.000 71.124 ;
    END
  END wd_in[218]
  PIN wd_in[219]
    DIRECTION INPUT ;
    USE SIGNAL ;
    PORT
      LAYER M4 ;
      RECT 1.000 71.232 3.000 71.256 ;
    END
    PORT
      LAYER M4 ;
      RECT 1.000 71.220 4.000 71.268 ;
    END
  END wd_in[219]
  PIN wd_in[220]
    DIRECTION INPUT ;
    USE SIGNAL ;
    PORT
      LAYER M4 ;
      RECT 1.000 71.376 3.000 71.400 ;
    END
    PORT
      LAYER M4 ;
      RECT 1.000 71.364 4.000 71.412 ;
    END
  END wd_in[220]
  PIN wd_in[221]
    DIRECTION INPUT ;
    USE SIGNAL ;
    PORT
      LAYER M4 ;
      RECT 1.000 71.520 3.000 71.544 ;
    END
    PORT
      LAYER M4 ;
      RECT 1.000 71.508 4.000 71.556 ;
    END
  END wd_in[221]
  PIN wd_in[222]
    DIRECTION INPUT ;
    USE SIGNAL ;
    PORT
      LAYER M4 ;
      RECT 1.000 71.664 3.000 71.688 ;
    END
    PORT
      LAYER M4 ;
      RECT 1.000 71.652 4.000 71.700 ;
    END
  END wd_in[222]
  PIN wd_in[223]
    DIRECTION INPUT ;
    USE SIGNAL ;
    PORT
      LAYER M4 ;
      RECT 1.000 71.808 3.000 71.832 ;
    END
    PORT
      LAYER M4 ;
      RECT 1.000 71.796 4.000 71.844 ;
    END
  END wd_in[223]
  PIN wd_in[224]
    DIRECTION INPUT ;
    USE SIGNAL ;
    PORT
      LAYER M4 ;
      RECT 1.000 71.952 3.000 71.976 ;
    END
    PORT
      LAYER M4 ;
      RECT 1.000 71.940 4.000 71.988 ;
    END
  END wd_in[224]
  PIN wd_in[225]
    DIRECTION INPUT ;
    USE SIGNAL ;
    PORT
      LAYER M4 ;
      RECT 1.000 72.096 3.000 72.120 ;
    END
    PORT
      LAYER M4 ;
      RECT 1.000 72.084 4.000 72.132 ;
    END
  END wd_in[225]
  PIN wd_in[226]
    DIRECTION INPUT ;
    USE SIGNAL ;
    PORT
      LAYER M4 ;
      RECT 1.000 72.240 3.000 72.264 ;
    END
    PORT
      LAYER M4 ;
      RECT 1.000 72.228 4.000 72.276 ;
    END
  END wd_in[226]
  PIN wd_in[227]
    DIRECTION INPUT ;
    USE SIGNAL ;
    PORT
      LAYER M4 ;
      RECT 1.000 72.384 3.000 72.408 ;
    END
    PORT
      LAYER M4 ;
      RECT 1.000 72.372 4.000 72.420 ;
    END
  END wd_in[227]
  PIN wd_in[228]
    DIRECTION INPUT ;
    USE SIGNAL ;
    PORT
      LAYER M4 ;
      RECT 1.000 72.528 3.000 72.552 ;
    END
    PORT
      LAYER M4 ;
      RECT 1.000 72.516 4.000 72.564 ;
    END
  END wd_in[228]
  PIN wd_in[229]
    DIRECTION INPUT ;
    USE SIGNAL ;
    PORT
      LAYER M4 ;
      RECT 1.000 72.672 3.000 72.696 ;
    END
    PORT
      LAYER M4 ;
      RECT 1.000 72.660 4.000 72.708 ;
    END
  END wd_in[229]
  PIN wd_in[230]
    DIRECTION INPUT ;
    USE SIGNAL ;
    PORT
      LAYER M4 ;
      RECT 1.000 72.816 3.000 72.840 ;
    END
    PORT
      LAYER M4 ;
      RECT 1.000 72.804 4.000 72.852 ;
    END
  END wd_in[230]
  PIN wd_in[231]
    DIRECTION INPUT ;
    USE SIGNAL ;
    PORT
      LAYER M4 ;
      RECT 1.000 72.960 3.000 72.984 ;
    END
    PORT
      LAYER M4 ;
      RECT 1.000 72.948 4.000 72.996 ;
    END
  END wd_in[231]
  PIN wd_in[232]
    DIRECTION INPUT ;
    USE SIGNAL ;
    PORT
      LAYER M4 ;
      RECT 1.000 73.104 3.000 73.128 ;
    END
    PORT
      LAYER M4 ;
      RECT 1.000 73.092 4.000 73.140 ;
    END
  END wd_in[232]
  PIN wd_in[233]
    DIRECTION INPUT ;
    USE SIGNAL ;
    PORT
      LAYER M4 ;
      RECT 1.000 73.248 3.000 73.272 ;
    END
    PORT
      LAYER M4 ;
      RECT 1.000 73.236 4.000 73.284 ;
    END
  END wd_in[233]
  PIN wd_in[234]
    DIRECTION INPUT ;
    USE SIGNAL ;
    PORT
      LAYER M4 ;
      RECT 1.000 73.392 3.000 73.416 ;
    END
    PORT
      LAYER M4 ;
      RECT 1.000 73.380 4.000 73.428 ;
    END
  END wd_in[234]
  PIN wd_in[235]
    DIRECTION INPUT ;
    USE SIGNAL ;
    PORT
      LAYER M4 ;
      RECT 1.000 73.536 3.000 73.560 ;
    END
    PORT
      LAYER M4 ;
      RECT 1.000 73.524 4.000 73.572 ;
    END
  END wd_in[235]
  PIN wd_in[236]
    DIRECTION INPUT ;
    USE SIGNAL ;
    PORT
      LAYER M4 ;
      RECT 1.000 73.680 3.000 73.704 ;
    END
    PORT
      LAYER M4 ;
      RECT 1.000 73.668 4.000 73.716 ;
    END
  END wd_in[236]
  PIN wd_in[237]
    DIRECTION INPUT ;
    USE SIGNAL ;
    PORT
      LAYER M4 ;
      RECT 1.000 73.824 3.000 73.848 ;
    END
    PORT
      LAYER M4 ;
      RECT 1.000 73.812 4.000 73.860 ;
    END
  END wd_in[237]
  PIN wd_in[238]
    DIRECTION INPUT ;
    USE SIGNAL ;
    PORT
      LAYER M4 ;
      RECT 1.000 73.968 3.000 73.992 ;
    END
    PORT
      LAYER M4 ;
      RECT 1.000 73.956 4.000 74.004 ;
    END
  END wd_in[238]
  PIN wd_in[239]
    DIRECTION INPUT ;
    USE SIGNAL ;
    PORT
      LAYER M4 ;
      RECT 1.000 74.112 3.000 74.136 ;
    END
    PORT
      LAYER M4 ;
      RECT 1.000 74.100 4.000 74.148 ;
    END
  END wd_in[239]
  PIN wd_in[240]
    DIRECTION INPUT ;
    USE SIGNAL ;
    PORT
      LAYER M4 ;
      RECT 1.000 74.256 3.000 74.280 ;
    END
    PORT
      LAYER M4 ;
      RECT 1.000 74.244 4.000 74.292 ;
    END
  END wd_in[240]
  PIN wd_in[241]
    DIRECTION INPUT ;
    USE SIGNAL ;
    PORT
      LAYER M4 ;
      RECT 1.000 74.400 3.000 74.424 ;
    END
    PORT
      LAYER M4 ;
      RECT 1.000 74.388 4.000 74.436 ;
    END
  END wd_in[241]
  PIN wd_in[242]
    DIRECTION INPUT ;
    USE SIGNAL ;
    PORT
      LAYER M4 ;
      RECT 1.000 74.544 3.000 74.568 ;
    END
    PORT
      LAYER M4 ;
      RECT 1.000 74.532 4.000 74.580 ;
    END
  END wd_in[242]
  PIN wd_in[243]
    DIRECTION INPUT ;
    USE SIGNAL ;
    PORT
      LAYER M4 ;
      RECT 1.000 74.688 3.000 74.712 ;
    END
    PORT
      LAYER M4 ;
      RECT 1.000 74.676 4.000 74.724 ;
    END
  END wd_in[243]
  PIN wd_in[244]
    DIRECTION INPUT ;
    USE SIGNAL ;
    PORT
      LAYER M4 ;
      RECT 1.000 74.832 3.000 74.856 ;
    END
    PORT
      LAYER M4 ;
      RECT 1.000 74.820 4.000 74.868 ;
    END
  END wd_in[244]
  PIN wd_in[245]
    DIRECTION INPUT ;
    USE SIGNAL ;
    PORT
      LAYER M4 ;
      RECT 1.000 74.976 3.000 75.000 ;
    END
    PORT
      LAYER M4 ;
      RECT 1.000 74.964 4.000 75.012 ;
    END
  END wd_in[245]
  PIN wd_in[246]
    DIRECTION INPUT ;
    USE SIGNAL ;
    PORT
      LAYER M4 ;
      RECT 1.000 75.120 3.000 75.144 ;
    END
    PORT
      LAYER M4 ;
      RECT 1.000 75.108 4.000 75.156 ;
    END
  END wd_in[246]
  PIN wd_in[247]
    DIRECTION INPUT ;
    USE SIGNAL ;
    PORT
      LAYER M4 ;
      RECT 1.000 75.264 3.000 75.288 ;
    END
    PORT
      LAYER M4 ;
      RECT 1.000 75.252 4.000 75.300 ;
    END
  END wd_in[247]
  PIN wd_in[248]
    DIRECTION INPUT ;
    USE SIGNAL ;
    PORT
      LAYER M4 ;
      RECT 1.000 75.408 3.000 75.432 ;
    END
    PORT
      LAYER M4 ;
      RECT 1.000 75.396 4.000 75.444 ;
    END
  END wd_in[248]
  PIN wd_in[249]
    DIRECTION INPUT ;
    USE SIGNAL ;
    PORT
      LAYER M4 ;
      RECT 1.000 75.552 3.000 75.576 ;
    END
    PORT
      LAYER M4 ;
      RECT 1.000 75.540 4.000 75.588 ;
    END
  END wd_in[249]
  PIN wd_in[250]
    DIRECTION INPUT ;
    USE SIGNAL ;
    PORT
      LAYER M4 ;
      RECT 1.000 75.696 3.000 75.720 ;
    END
    PORT
      LAYER M4 ;
      RECT 1.000 75.684 4.000 75.732 ;
    END
  END wd_in[250]
  PIN wd_in[251]
    DIRECTION INPUT ;
    USE SIGNAL ;
    PORT
      LAYER M4 ;
      RECT 1.000 75.840 3.000 75.864 ;
    END
    PORT
      LAYER M4 ;
      RECT 1.000 75.828 4.000 75.876 ;
    END
  END wd_in[251]
  PIN wd_in[252]
    DIRECTION INPUT ;
    USE SIGNAL ;
    PORT
      LAYER M4 ;
      RECT 1.000 75.984 3.000 76.008 ;
    END
    PORT
      LAYER M4 ;
      RECT 1.000 75.972 4.000 76.020 ;
    END
  END wd_in[252]
  PIN wd_in[253]
    DIRECTION INPUT ;
    USE SIGNAL ;
    PORT
      LAYER M4 ;
      RECT 1.000 76.128 3.000 76.152 ;
    END
    PORT
      LAYER M4 ;
      RECT 1.000 76.116 4.000 76.164 ;
    END
  END wd_in[253]
  PIN wd_in[254]
    DIRECTION INPUT ;
    USE SIGNAL ;
    PORT
      LAYER M4 ;
      RECT 1.000 76.272 3.000 76.296 ;
    END
    PORT
      LAYER M4 ;
      RECT 1.000 76.260 4.000 76.308 ;
    END
  END wd_in[254]
  PIN wd_in[255]
    DIRECTION INPUT ;
    USE SIGNAL ;
    PORT
      LAYER M4 ;
      RECT 1.000 76.416 3.000 76.440 ;
    END
    PORT
      LAYER M4 ;
      RECT 1.000 76.404 4.000 76.452 ;
    END
  END wd_in[255]
  PIN addr_in[0]
    DIRECTION INPUT ;
    USE SIGNAL ;
    PORT
      LAYER M4 ;
      RECT 1.000 79.344 3.000 79.368 ;
    END
    PORT
      LAYER M4 ;
      RECT 1.000 79.332 4.000 79.380 ;
    END
  END addr_in[0]
  PIN addr_in[1]
    DIRECTION INPUT ;
    USE SIGNAL ;
    PORT
      LAYER M4 ;
      RECT 1.000 79.488 3.000 79.512 ;
    END
    PORT
      LAYER M4 ;
      RECT 1.000 79.476 4.000 79.524 ;
    END
  END addr_in[1]
  PIN addr_in[2]
    DIRECTION INPUT ;
    USE SIGNAL ;
    PORT
      LAYER M4 ;
      RECT 1.000 79.632 3.000 79.656 ;
    END
    PORT
      LAYER M4 ;
      RECT 1.000 79.620 4.000 79.668 ;
    END
  END addr_in[2]
  PIN addr_in[3]
    DIRECTION INPUT ;
    USE SIGNAL ;
    PORT
      LAYER M4 ;
      RECT 1.000 79.776 3.000 79.800 ;
    END
    PORT
      LAYER M4 ;
      RECT 1.000 79.764 4.000 79.812 ;
    END
  END addr_in[3]
  PIN addr_in[4]
    DIRECTION INPUT ;
    USE SIGNAL ;
    PORT
      LAYER M4 ;
      RECT 1.000 79.920 3.000 79.944 ;
    END
    PORT
      LAYER M4 ;
      RECT 1.000 79.908 4.000 79.956 ;
    END
  END addr_in[4]
  PIN addr_in[5]
    DIRECTION INPUT ;
    USE SIGNAL ;
    PORT
      LAYER M4 ;
      RECT 1.000 80.064 3.000 80.088 ;
    END
    PORT
      LAYER M4 ;
      RECT 1.000 80.052 4.000 80.100 ;
    END
  END addr_in[5]
  PIN addr_in[6]
    DIRECTION INPUT ;
    USE SIGNAL ;
    PORT
      LAYER M4 ;
      RECT 1.000 80.208 3.000 80.232 ;
    END
    PORT
      LAYER M4 ;
      RECT 1.000 80.196 4.000 80.244 ;
    END
  END addr_in[6]
  PIN addr_in[7]
    DIRECTION INPUT ;
    USE SIGNAL ;
    PORT
      LAYER M4 ;
      RECT 1.000 80.352 3.000 80.376 ;
    END
    PORT
      LAYER M4 ;
      RECT 1.000 80.340 4.000 80.388 ;
    END
  END addr_in[7]
  PIN addr_in[8]
    DIRECTION INPUT ;
    USE SIGNAL ;
    PORT
      LAYER M4 ;
      RECT 1.000 80.496 3.000 80.520 ;
    END
    PORT
      LAYER M4 ;
      RECT 1.000 80.484 4.000 80.532 ;
    END
  END addr_in[8]
  PIN we_in
    DIRECTION INPUT ;
    USE SIGNAL ;
    PORT
      LAYER M4 ;
      RECT 1.000 83.424 3.000 83.448 ;
    END
    PORT
      LAYER M4 ;
      RECT 1.000 83.412 4.000 83.460 ;
    END
  END we_in
  PIN ce_in
    DIRECTION INPUT ;
    USE SIGNAL ;
    PORT
      LAYER M4 ;
      RECT 1.000 83.568 3.000 83.592 ;
    END
    PORT
      LAYER M4 ;
      RECT 1.000 83.556 4.000 83.604 ;
    END
  END ce_in
  PIN clk
    DIRECTION INPUT ;
    USE SIGNAL ;
    PORT
      LAYER M4 ;
      RECT 1.000 83.712 3.000 83.736 ;
    END
    PORT
      LAYER M4 ;
      RECT 1.000 83.700 4.000 83.748 ;
    END
  END clk
  PIN VSS
    DIRECTION INOUT ;
    USE GROUND ;
    PORT
      LAYER M4 ;
      RECT 0.048 0.000 66.452 0.096 ;
      RECT 0.048 0.768 66.452 0.864 ;
      RECT 0.048 1.536 66.452 1.632 ;
      RECT 0.048 2.304 66.452 2.400 ;
      RECT 0.048 3.072 66.452 3.168 ;
      RECT 0.048 3.840 66.452 3.936 ;
      RECT 0.048 4.608 66.452 4.704 ;
      RECT 0.048 5.376 66.452 5.472 ;
      RECT 0.048 6.144 66.452 6.240 ;
      RECT 0.048 6.912 66.452 7.008 ;
      RECT 0.048 7.680 66.452 7.776 ;
      RECT 0.048 8.448 66.452 8.544 ;
      RECT 0.048 9.216 66.452 9.312 ;
      RECT 0.048 9.984 66.452 10.080 ;
      RECT 0.048 10.752 66.452 10.848 ;
      RECT 0.048 11.520 66.452 11.616 ;
      RECT 0.048 12.288 66.452 12.384 ;
      RECT 0.048 13.056 66.452 13.152 ;
      RECT 0.048 13.824 66.452 13.920 ;
      RECT 0.048 14.592 66.452 14.688 ;
      RECT 0.048 15.360 66.452 15.456 ;
      RECT 0.048 16.128 66.452 16.224 ;
      RECT 0.048 16.896 66.452 16.992 ;
      RECT 0.048 17.664 66.452 17.760 ;
      RECT 0.048 18.432 66.452 18.528 ;
      RECT 0.048 19.200 66.452 19.296 ;
      RECT 0.048 19.968 66.452 20.064 ;
      RECT 0.048 20.736 66.452 20.832 ;
      RECT 0.048 21.504 66.452 21.600 ;
      RECT 0.048 22.272 66.452 22.368 ;
      RECT 0.048 23.040 66.452 23.136 ;
      RECT 0.048 23.808 66.452 23.904 ;
      RECT 0.048 24.576 66.452 24.672 ;
      RECT 0.048 25.344 66.452 25.440 ;
      RECT 0.048 26.112 66.452 26.208 ;
      RECT 0.048 26.880 66.452 26.976 ;
      RECT 0.048 27.648 66.452 27.744 ;
      RECT 0.048 28.416 66.452 28.512 ;
      RECT 0.048 29.184 66.452 29.280 ;
      RECT 0.048 29.952 66.452 30.048 ;
      RECT 0.048 30.720 66.452 30.816 ;
      RECT 0.048 31.488 66.452 31.584 ;
      RECT 0.048 32.256 66.452 32.352 ;
      RECT 0.048 33.024 66.452 33.120 ;
      RECT 0.048 33.792 66.452 33.888 ;
      RECT 0.048 34.560 66.452 34.656 ;
      RECT 0.048 35.328 66.452 35.424 ;
      RECT 0.048 36.096 66.452 36.192 ;
      RECT 0.048 36.864 66.452 36.960 ;
      RECT 0.048 37.632 66.452 37.728 ;
      RECT 0.048 38.400 66.452 38.496 ;
      RECT 0.048 39.168 66.452 39.264 ;
      RECT 0.048 39.936 66.452 40.032 ;
      RECT 0.048 40.704 66.452 40.800 ;
      RECT 0.048 41.472 66.452 41.568 ;
      RECT 0.048 42.240 66.452 42.336 ;
      RECT 0.048 43.008 66.452 43.104 ;
      RECT 0.048 43.776 66.452 43.872 ;
      RECT 0.048 44.544 66.452 44.640 ;
      RECT 0.048 45.312 66.452 45.408 ;
      RECT 0.048 46.080 66.452 46.176 ;
      RECT 0.048 46.848 66.452 46.944 ;
      RECT 0.048 47.616 66.452 47.712 ;
      RECT 0.048 48.384 66.452 48.480 ;
      RECT 0.048 49.152 66.452 49.248 ;
      RECT 0.048 49.920 66.452 50.016 ;
      RECT 0.048 50.688 66.452 50.784 ;
      RECT 0.048 51.456 66.452 51.552 ;
      RECT 0.048 52.224 66.452 52.320 ;
      RECT 0.048 52.992 66.452 53.088 ;
      RECT 0.048 53.760 66.452 53.856 ;
      RECT 0.048 54.528 66.452 54.624 ;
      RECT 0.048 55.296 66.452 55.392 ;
      RECT 0.048 56.064 66.452 56.160 ;
      RECT 0.048 56.832 66.452 56.928 ;
      RECT 0.048 57.600 66.452 57.696 ;
      RECT 0.048 58.368 66.452 58.464 ;
      RECT 0.048 59.136 66.452 59.232 ;
      RECT 0.048 59.904 66.452 60.000 ;
      RECT 0.048 60.672 66.452 60.768 ;
      RECT 0.048 61.440 66.452 61.536 ;
      RECT 0.048 62.208 66.452 62.304 ;
      RECT 0.048 62.976 66.452 63.072 ;
      RECT 0.048 63.744 66.452 63.840 ;
      RECT 0.048 64.512 66.452 64.608 ;
      RECT 0.048 65.280 66.452 65.376 ;
      RECT 0.048 66.048 66.452 66.144 ;
      RECT 0.048 66.816 66.452 66.912 ;
      RECT 0.048 67.584 66.452 67.680 ;
      RECT 0.048 68.352 66.452 68.448 ;
      RECT 0.048 69.120 66.452 69.216 ;
      RECT 0.048 69.888 66.452 69.984 ;
      RECT 0.048 70.656 66.452 70.752 ;
      RECT 0.048 71.424 66.452 71.520 ;
      RECT 0.048 72.192 66.452 72.288 ;
      RECT 0.048 72.960 66.452 73.056 ;
      RECT 0.048 73.728 66.452 73.824 ;
      RECT 0.048 74.496 66.452 74.592 ;
      RECT 0.048 75.264 66.452 75.360 ;
      RECT 0.048 76.032 66.452 76.128 ;
      RECT 0.048 76.800 66.452 76.896 ;
      RECT 0.048 77.568 66.452 77.664 ;
      RECT 0.048 78.336 66.452 78.432 ;
      RECT 0.048 79.104 66.452 79.200 ;
      RECT 0.048 79.872 66.452 79.968 ;
      RECT 0.048 80.640 66.452 80.736 ;
      RECT 0.048 81.408 66.452 81.504 ;
      RECT 0.048 82.176 66.452 82.272 ;
      RECT 0.048 82.944 66.452 83.040 ;
      RECT 0.048 83.712 66.452 83.808 ;
    END
  END VSS
  PIN VDD
    DIRECTION INOUT ;
    USE POWER ;
    PORT
      LAYER M4 ;
      RECT 0.048 0.384 66.452 0.480 ;
      RECT 0.048 1.152 66.452 1.248 ;
      RECT 0.048 1.920 66.452 2.016 ;
      RECT 0.048 2.688 66.452 2.784 ;
      RECT 0.048 3.456 66.452 3.552 ;
      RECT 0.048 4.224 66.452 4.320 ;
      RECT 0.048 4.992 66.452 5.088 ;
      RECT 0.048 5.760 66.452 5.856 ;
      RECT 0.048 6.528 66.452 6.624 ;
      RECT 0.048 7.296 66.452 7.392 ;
      RECT 0.048 8.064 66.452 8.160 ;
      RECT 0.048 8.832 66.452 8.928 ;
      RECT 0.048 9.600 66.452 9.696 ;
      RECT 0.048 10.368 66.452 10.464 ;
      RECT 0.048 11.136 66.452 11.232 ;
      RECT 0.048 11.904 66.452 12.000 ;
      RECT 0.048 12.672 66.452 12.768 ;
      RECT 0.048 13.440 66.452 13.536 ;
      RECT 0.048 14.208 66.452 14.304 ;
      RECT 0.048 14.976 66.452 15.072 ;
      RECT 0.048 15.744 66.452 15.840 ;
      RECT 0.048 16.512 66.452 16.608 ;
      RECT 0.048 17.280 66.452 17.376 ;
      RECT 0.048 18.048 66.452 18.144 ;
      RECT 0.048 18.816 66.452 18.912 ;
      RECT 0.048 19.584 66.452 19.680 ;
      RECT 0.048 20.352 66.452 20.448 ;
      RECT 0.048 21.120 66.452 21.216 ;
      RECT 0.048 21.888 66.452 21.984 ;
      RECT 0.048 22.656 66.452 22.752 ;
      RECT 0.048 23.424 66.452 23.520 ;
      RECT 0.048 24.192 66.452 24.288 ;
      RECT 0.048 24.960 66.452 25.056 ;
      RECT 0.048 25.728 66.452 25.824 ;
      RECT 0.048 26.496 66.452 26.592 ;
      RECT 0.048 27.264 66.452 27.360 ;
      RECT 0.048 28.032 66.452 28.128 ;
      RECT 0.048 28.800 66.452 28.896 ;
      RECT 0.048 29.568 66.452 29.664 ;
      RECT 0.048 30.336 66.452 30.432 ;
      RECT 0.048 31.104 66.452 31.200 ;
      RECT 0.048 31.872 66.452 31.968 ;
      RECT 0.048 32.640 66.452 32.736 ;
      RECT 0.048 33.408 66.452 33.504 ;
      RECT 0.048 34.176 66.452 34.272 ;
      RECT 0.048 34.944 66.452 35.040 ;
      RECT 0.048 35.712 66.452 35.808 ;
      RECT 0.048 36.480 66.452 36.576 ;
      RECT 0.048 37.248 66.452 37.344 ;
      RECT 0.048 38.016 66.452 38.112 ;
      RECT 0.048 38.784 66.452 38.880 ;
      RECT 0.048 39.552 66.452 39.648 ;
      RECT 0.048 40.320 66.452 40.416 ;
      RECT 0.048 41.088 66.452 41.184 ;
      RECT 0.048 41.856 66.452 41.952 ;
      RECT 0.048 42.624 66.452 42.720 ;
      RECT 0.048 43.392 66.452 43.488 ;
      RECT 0.048 44.160 66.452 44.256 ;
      RECT 0.048 44.928 66.452 45.024 ;
      RECT 0.048 45.696 66.452 45.792 ;
      RECT 0.048 46.464 66.452 46.560 ;
      RECT 0.048 47.232 66.452 47.328 ;
      RECT 0.048 48.000 66.452 48.096 ;
      RECT 0.048 48.768 66.452 48.864 ;
      RECT 0.048 49.536 66.452 49.632 ;
      RECT 0.048 50.304 66.452 50.400 ;
      RECT 0.048 51.072 66.452 51.168 ;
      RECT 0.048 51.840 66.452 51.936 ;
      RECT 0.048 52.608 66.452 52.704 ;
      RECT 0.048 53.376 66.452 53.472 ;
      RECT 0.048 54.144 66.452 54.240 ;
      RECT 0.048 54.912 66.452 55.008 ;
      RECT 0.048 55.680 66.452 55.776 ;
      RECT 0.048 56.448 66.452 56.544 ;
      RECT 0.048 57.216 66.452 57.312 ;
      RECT 0.048 57.984 66.452 58.080 ;
      RECT 0.048 58.752 66.452 58.848 ;
      RECT 0.048 59.520 66.452 59.616 ;
      RECT 0.048 60.288 66.452 60.384 ;
      RECT 0.048 61.056 66.452 61.152 ;
      RECT 0.048 61.824 66.452 61.920 ;
      RECT 0.048 62.592 66.452 62.688 ;
      RECT 0.048 63.360 66.452 63.456 ;
      RECT 0.048 64.128 66.452 64.224 ;
      RECT 0.048 64.896 66.452 64.992 ;
      RECT 0.048 65.664 66.452 65.760 ;
      RECT 0.048 66.432 66.452 66.528 ;
      RECT 0.048 67.200 66.452 67.296 ;
      RECT 0.048 67.968 66.452 68.064 ;
      RECT 0.048 68.736 66.452 68.832 ;
      RECT 0.048 69.504 66.452 69.600 ;
      RECT 0.048 70.272 66.452 70.368 ;
      RECT 0.048 71.040 66.452 71.136 ;
      RECT 0.048 71.808 66.452 71.904 ;
      RECT 0.048 72.576 66.452 72.672 ;
      RECT 0.048 73.344 66.452 73.440 ;
      RECT 0.048 74.112 66.452 74.208 ;
      RECT 0.048 74.880 66.452 74.976 ;
      RECT 0.048 75.648 66.452 75.744 ;
      RECT 0.048 76.416 66.452 76.512 ;
      RECT 0.048 77.184 66.452 77.280 ;
      RECT 0.048 77.952 66.452 78.048 ;
      RECT 0.048 78.720 66.452 78.816 ;
      RECT 0.048 79.488 66.452 79.584 ;
      RECT 0.048 80.256 66.452 80.352 ;
      RECT 0.048 81.024 66.452 81.120 ;
      RECT 0.048 81.792 66.452 81.888 ;
      RECT 0.048 82.560 66.452 82.656 ;
      RECT 0.048 83.328 66.452 83.424 ;
    END
  END VDD
  OBS
    LAYER M1 ;
    RECT 0 0 66.500 84.000 ;
    LAYER M2 ;
    RECT 0 0 66.500 84.000 ;
    LAYER M3 ;
    RECT 0 0 66.500 84.000 ;
  END
END fakeram_256x512
END LIBRARY
